VERSION 5.8 ;
BUSBITCHARS "[]" ;
DIVIDERCHAR "/" ;
UNITS
    DATABASE MICRONS 1000 ;
END UNITS

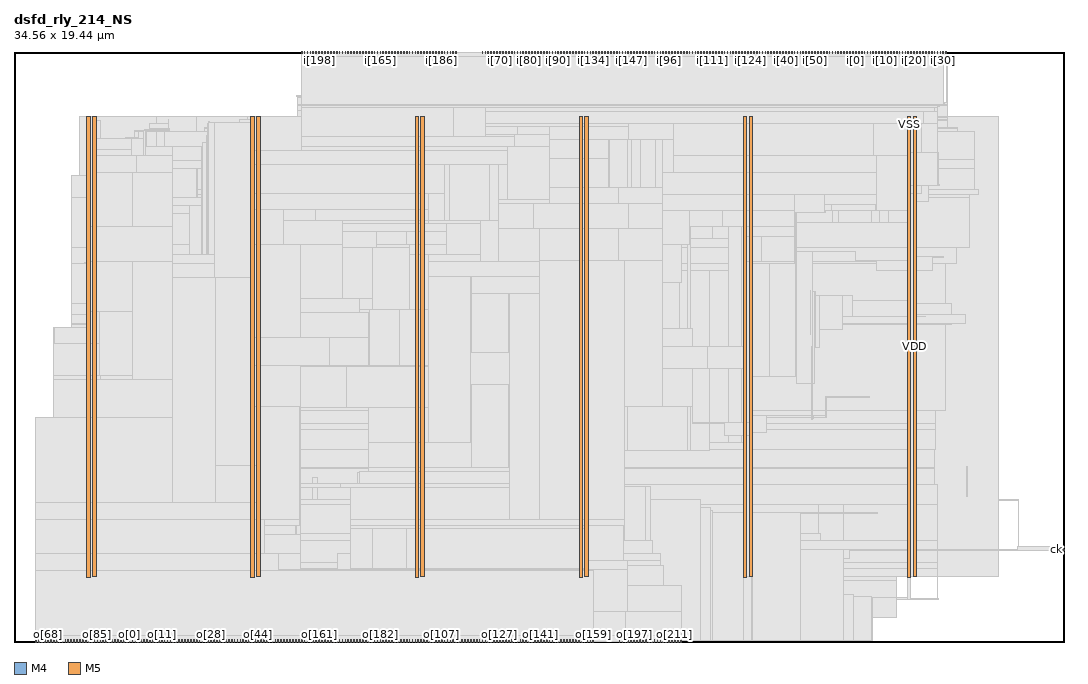
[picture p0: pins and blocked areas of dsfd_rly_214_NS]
MACRO dsfd_rly_214_NS
  FOREIGN dsfd_rly_214_NS 0 0 ;
  CLASS BLOCK ;
  SIZE 34.56 BY 19.44 ;
  PIN ck
    DIRECTION INPUT ;
    USE SIGNAL ;
    PORT
      LAYER M4 ;
        RECT  34.476 3.024 34.56 3.048 ;
    END
  END ck
  PIN i[0]
    DIRECTION INPUT ;
    USE SIGNAL ;
    PORT
      LAYER M5 ;
        RECT  27.696 19.356 27.72 19.44 ;
    END
  END i[0]
  PIN i[100]
    DIRECTION INPUT ;
    USE SIGNAL ;
    PORT
      LAYER M5 ;
        RECT  21.936 19.356 21.96 19.44 ;
    END
  END i[100]
  PIN i[101]
    DIRECTION INPUT ;
    USE SIGNAL ;
    PORT
      LAYER M5 ;
        RECT  22.032 19.356 22.056 19.44 ;
    END
  END i[101]
  PIN i[102]
    DIRECTION INPUT ;
    USE SIGNAL ;
    PORT
      LAYER M5 ;
        RECT  22.128 19.356 22.152 19.44 ;
    END
  END i[102]
  PIN i[103]
    DIRECTION INPUT ;
    USE SIGNAL ;
    PORT
      LAYER M5 ;
        RECT  22.224 19.356 22.248 19.44 ;
    END
  END i[103]
  PIN i[104]
    DIRECTION INPUT ;
    USE SIGNAL ;
    PORT
      LAYER M5 ;
        RECT  22.32 19.356 22.344 19.44 ;
    END
  END i[104]
  PIN i[105]
    DIRECTION INPUT ;
    USE SIGNAL ;
    PORT
      LAYER M5 ;
        RECT  22.416 19.356 22.44 19.44 ;
    END
  END i[105]
  PIN i[106]
    DIRECTION INPUT ;
    USE SIGNAL ;
    PORT
      LAYER M5 ;
        RECT  22.512 19.356 22.536 19.44 ;
    END
  END i[106]
  PIN i[107]
    DIRECTION INPUT ;
    USE SIGNAL ;
    PORT
      LAYER M5 ;
        RECT  22.608 19.356 22.632 19.44 ;
    END
  END i[107]
  PIN i[108]
    DIRECTION INPUT ;
    USE SIGNAL ;
    PORT
      LAYER M5 ;
        RECT  22.704 19.356 22.728 19.44 ;
    END
  END i[108]
  PIN i[109]
    DIRECTION INPUT ;
    USE SIGNAL ;
    PORT
      LAYER M5 ;
        RECT  22.8 19.356 22.824 19.44 ;
    END
  END i[109]
  PIN i[10]
    DIRECTION INPUT ;
    USE SIGNAL ;
    PORT
      LAYER M5 ;
        RECT  28.656 19.356 28.68 19.44 ;
    END
  END i[10]
  PIN i[110]
    DIRECTION INPUT ;
    USE SIGNAL ;
    PORT
      LAYER M5 ;
        RECT  22.896 19.356 22.92 19.44 ;
    END
  END i[110]
  PIN i[111]
    DIRECTION INPUT ;
    USE SIGNAL ;
    PORT
      LAYER M5 ;
        RECT  22.992 19.356 23.016 19.44 ;
    END
  END i[111]
  PIN i[112]
    DIRECTION INPUT ;
    USE SIGNAL ;
    PORT
      LAYER M5 ;
        RECT  23.088 19.356 23.112 19.44 ;
    END
  END i[112]
  PIN i[113]
    DIRECTION INPUT ;
    USE SIGNAL ;
    PORT
      LAYER M5 ;
        RECT  23.184 19.356 23.208 19.44 ;
    END
  END i[113]
  PIN i[114]
    DIRECTION INPUT ;
    USE SIGNAL ;
    PORT
      LAYER M5 ;
        RECT  23.28 19.356 23.304 19.44 ;
    END
  END i[114]
  PIN i[115]
    DIRECTION INPUT ;
    USE SIGNAL ;
    PORT
      LAYER M5 ;
        RECT  23.376 19.356 23.4 19.44 ;
    END
  END i[115]
  PIN i[116]
    DIRECTION INPUT ;
    USE SIGNAL ;
    PORT
      LAYER M5 ;
        RECT  23.472 19.356 23.496 19.44 ;
    END
  END i[116]
  PIN i[117]
    DIRECTION INPUT ;
    USE SIGNAL ;
    PORT
      LAYER M5 ;
        RECT  23.568 19.356 23.592 19.44 ;
    END
  END i[117]
  PIN i[118]
    DIRECTION INPUT ;
    USE SIGNAL ;
    PORT
      LAYER M5 ;
        RECT  23.664 19.356 23.688 19.44 ;
    END
  END i[118]
  PIN i[119]
    DIRECTION INPUT ;
    USE SIGNAL ;
    PORT
      LAYER M5 ;
        RECT  23.76 19.356 23.784 19.44 ;
    END
  END i[119]
  PIN i[11]
    DIRECTION INPUT ;
    USE SIGNAL ;
    PORT
      LAYER M5 ;
        RECT  28.752 19.356 28.776 19.44 ;
    END
  END i[11]
  PIN i[120]
    DIRECTION INPUT ;
    USE SIGNAL ;
    PORT
      LAYER M5 ;
        RECT  23.856 19.356 23.88 19.44 ;
    END
  END i[120]
  PIN i[121]
    DIRECTION INPUT ;
    USE SIGNAL ;
    PORT
      LAYER M5 ;
        RECT  23.952 19.356 23.976 19.44 ;
    END
  END i[121]
  PIN i[122]
    DIRECTION INPUT ;
    USE SIGNAL ;
    PORT
      LAYER M5 ;
        RECT  24.048 19.356 24.072 19.44 ;
    END
  END i[122]
  PIN i[123]
    DIRECTION INPUT ;
    USE SIGNAL ;
    PORT
      LAYER M5 ;
        RECT  24.144 19.356 24.168 19.44 ;
    END
  END i[123]
  PIN i[124]
    DIRECTION INPUT ;
    USE SIGNAL ;
    PORT
      LAYER M5 ;
        RECT  24.24 19.356 24.264 19.44 ;
    END
  END i[124]
  PIN i[125]
    DIRECTION INPUT ;
    USE SIGNAL ;
    PORT
      LAYER M5 ;
        RECT  24.336 19.356 24.36 19.44 ;
    END
  END i[125]
  PIN i[126]
    DIRECTION INPUT ;
    USE SIGNAL ;
    PORT
      LAYER M5 ;
        RECT  24.432 19.356 24.456 19.44 ;
    END
  END i[126]
  PIN i[127]
    DIRECTION INPUT ;
    USE SIGNAL ;
    PORT
      LAYER M5 ;
        RECT  24.528 19.356 24.552 19.44 ;
    END
  END i[127]
  PIN i[128]
    DIRECTION INPUT ;
    USE SIGNAL ;
    PORT
      LAYER M5 ;
        RECT  18.48 19.356 18.504 19.44 ;
    END
  END i[128]
  PIN i[129]
    DIRECTION INPUT ;
    USE SIGNAL ;
    PORT
      LAYER M5 ;
        RECT  18.576 19.356 18.6 19.44 ;
    END
  END i[129]
  PIN i[12]
    DIRECTION INPUT ;
    USE SIGNAL ;
    PORT
      LAYER M5 ;
        RECT  28.848 19.356 28.872 19.44 ;
    END
  END i[12]
  PIN i[130]
    DIRECTION INPUT ;
    USE SIGNAL ;
    PORT
      LAYER M5 ;
        RECT  18.672 19.356 18.696 19.44 ;
    END
  END i[130]
  PIN i[131]
    DIRECTION INPUT ;
    USE SIGNAL ;
    PORT
      LAYER M5 ;
        RECT  18.768 19.356 18.792 19.44 ;
    END
  END i[131]
  PIN i[132]
    DIRECTION INPUT ;
    USE SIGNAL ;
    PORT
      LAYER M5 ;
        RECT  18.864 19.356 18.888 19.44 ;
    END
  END i[132]
  PIN i[133]
    DIRECTION INPUT ;
    USE SIGNAL ;
    PORT
      LAYER M5 ;
        RECT  18.96 19.356 18.984 19.44 ;
    END
  END i[133]
  PIN i[134]
    DIRECTION INPUT ;
    USE SIGNAL ;
    PORT
      LAYER M5 ;
        RECT  19.056 19.356 19.08 19.44 ;
    END
  END i[134]
  PIN i[135]
    DIRECTION INPUT ;
    USE SIGNAL ;
    PORT
      LAYER M5 ;
        RECT  19.152 19.356 19.176 19.44 ;
    END
  END i[135]
  PIN i[136]
    DIRECTION INPUT ;
    USE SIGNAL ;
    PORT
      LAYER M5 ;
        RECT  19.248 19.356 19.272 19.44 ;
    END
  END i[136]
  PIN i[137]
    DIRECTION INPUT ;
    USE SIGNAL ;
    PORT
      LAYER M5 ;
        RECT  19.344 19.356 19.368 19.44 ;
    END
  END i[137]
  PIN i[138]
    DIRECTION INPUT ;
    USE SIGNAL ;
    PORT
      LAYER M5 ;
        RECT  19.44 19.356 19.464 19.44 ;
    END
  END i[138]
  PIN i[139]
    DIRECTION INPUT ;
    USE SIGNAL ;
    PORT
      LAYER M5 ;
        RECT  19.536 19.356 19.56 19.44 ;
    END
  END i[139]
  PIN i[13]
    DIRECTION INPUT ;
    USE SIGNAL ;
    PORT
      LAYER M5 ;
        RECT  28.944 19.356 28.968 19.44 ;
    END
  END i[13]
  PIN i[140]
    DIRECTION INPUT ;
    USE SIGNAL ;
    PORT
      LAYER M5 ;
        RECT  19.632 19.356 19.656 19.44 ;
    END
  END i[140]
  PIN i[141]
    DIRECTION INPUT ;
    USE SIGNAL ;
    PORT
      LAYER M5 ;
        RECT  19.728 19.356 19.752 19.44 ;
    END
  END i[141]
  PIN i[142]
    DIRECTION INPUT ;
    USE SIGNAL ;
    PORT
      LAYER M5 ;
        RECT  19.824 19.356 19.848 19.44 ;
    END
  END i[142]
  PIN i[143]
    DIRECTION INPUT ;
    USE SIGNAL ;
    PORT
      LAYER M5 ;
        RECT  19.92 19.356 19.944 19.44 ;
    END
  END i[143]
  PIN i[144]
    DIRECTION INPUT ;
    USE SIGNAL ;
    PORT
      LAYER M5 ;
        RECT  20.016 19.356 20.04 19.44 ;
    END
  END i[144]
  PIN i[145]
    DIRECTION INPUT ;
    USE SIGNAL ;
    PORT
      LAYER M5 ;
        RECT  20.112 19.356 20.136 19.44 ;
    END
  END i[145]
  PIN i[146]
    DIRECTION INPUT ;
    USE SIGNAL ;
    PORT
      LAYER M5 ;
        RECT  20.208 19.356 20.232 19.44 ;
    END
  END i[146]
  PIN i[147]
    DIRECTION INPUT ;
    USE SIGNAL ;
    PORT
      LAYER M5 ;
        RECT  20.304 19.356 20.328 19.44 ;
    END
  END i[147]
  PIN i[148]
    DIRECTION INPUT ;
    USE SIGNAL ;
    PORT
      LAYER M5 ;
        RECT  20.4 19.356 20.424 19.44 ;
    END
  END i[148]
  PIN i[149]
    DIRECTION INPUT ;
    USE SIGNAL ;
    PORT
      LAYER M5 ;
        RECT  20.496 19.356 20.52 19.44 ;
    END
  END i[149]
  PIN i[14]
    DIRECTION INPUT ;
    USE SIGNAL ;
    PORT
      LAYER M5 ;
        RECT  29.04 19.356 29.064 19.44 ;
    END
  END i[14]
  PIN i[150]
    DIRECTION INPUT ;
    USE SIGNAL ;
    PORT
      LAYER M5 ;
        RECT  20.592 19.356 20.616 19.44 ;
    END
  END i[150]
  PIN i[151]
    DIRECTION INPUT ;
    USE SIGNAL ;
    PORT
      LAYER M5 ;
        RECT  20.688 19.356 20.712 19.44 ;
    END
  END i[151]
  PIN i[152]
    DIRECTION INPUT ;
    USE SIGNAL ;
    PORT
      LAYER M5 ;
        RECT  20.784 19.356 20.808 19.44 ;
    END
  END i[152]
  PIN i[153]
    DIRECTION INPUT ;
    USE SIGNAL ;
    PORT
      LAYER M5 ;
        RECT  20.88 19.356 20.904 19.44 ;
    END
  END i[153]
  PIN i[154]
    DIRECTION INPUT ;
    USE SIGNAL ;
    PORT
      LAYER M5 ;
        RECT  20.976 19.356 21 19.44 ;
    END
  END i[154]
  PIN i[155]
    DIRECTION INPUT ;
    USE SIGNAL ;
    PORT
      LAYER M5 ;
        RECT  21.072 19.356 21.096 19.44 ;
    END
  END i[155]
  PIN i[156]
    DIRECTION INPUT ;
    USE SIGNAL ;
    PORT
      LAYER M5 ;
        RECT  21.168 19.356 21.192 19.44 ;
    END
  END i[156]
  PIN i[157]
    DIRECTION INPUT ;
    USE SIGNAL ;
    PORT
      LAYER M5 ;
        RECT  21.264 19.356 21.288 19.44 ;
    END
  END i[157]
  PIN i[158]
    DIRECTION INPUT ;
    USE SIGNAL ;
    PORT
      LAYER M5 ;
        RECT  21.36 19.356 21.384 19.44 ;
    END
  END i[158]
  PIN i[159]
    DIRECTION INPUT ;
    USE SIGNAL ;
    PORT
      LAYER M5 ;
        RECT  21.456 19.356 21.48 19.44 ;
    END
  END i[159]
  PIN i[15]
    DIRECTION INPUT ;
    USE SIGNAL ;
    PORT
      LAYER M5 ;
        RECT  29.136 19.356 29.16 19.44 ;
    END
  END i[15]
  PIN i[160]
    DIRECTION INPUT ;
    USE SIGNAL ;
    PORT
      LAYER M5 ;
        RECT  11.568 19.356 11.592 19.44 ;
    END
  END i[160]
  PIN i[161]
    DIRECTION INPUT ;
    USE SIGNAL ;
    PORT
      LAYER M5 ;
        RECT  11.664 19.356 11.688 19.44 ;
    END
  END i[161]
  PIN i[162]
    DIRECTION INPUT ;
    USE SIGNAL ;
    PORT
      LAYER M5 ;
        RECT  11.76 19.356 11.784 19.44 ;
    END
  END i[162]
  PIN i[163]
    DIRECTION INPUT ;
    USE SIGNAL ;
    PORT
      LAYER M5 ;
        RECT  11.856 19.356 11.88 19.44 ;
    END
  END i[163]
  PIN i[164]
    DIRECTION INPUT ;
    USE SIGNAL ;
    PORT
      LAYER M5 ;
        RECT  11.952 19.356 11.976 19.44 ;
    END
  END i[164]
  PIN i[165]
    DIRECTION INPUT ;
    USE SIGNAL ;
    PORT
      LAYER M5 ;
        RECT  12.048 19.356 12.072 19.44 ;
    END
  END i[165]
  PIN i[166]
    DIRECTION INPUT ;
    USE SIGNAL ;
    PORT
      LAYER M5 ;
        RECT  12.144 19.356 12.168 19.44 ;
    END
  END i[166]
  PIN i[167]
    DIRECTION INPUT ;
    USE SIGNAL ;
    PORT
      LAYER M5 ;
        RECT  12.24 19.356 12.264 19.44 ;
    END
  END i[167]
  PIN i[168]
    DIRECTION INPUT ;
    USE SIGNAL ;
    PORT
      LAYER M5 ;
        RECT  12.336 19.356 12.36 19.44 ;
    END
  END i[168]
  PIN i[169]
    DIRECTION INPUT ;
    USE SIGNAL ;
    PORT
      LAYER M5 ;
        RECT  12.432 19.356 12.456 19.44 ;
    END
  END i[169]
  PIN i[16]
    DIRECTION INPUT ;
    USE SIGNAL ;
    PORT
      LAYER M5 ;
        RECT  29.232 19.356 29.256 19.44 ;
    END
  END i[16]
  PIN i[170]
    DIRECTION INPUT ;
    USE SIGNAL ;
    PORT
      LAYER M5 ;
        RECT  12.528 19.356 12.552 19.44 ;
    END
  END i[170]
  PIN i[171]
    DIRECTION INPUT ;
    USE SIGNAL ;
    PORT
      LAYER M5 ;
        RECT  12.624 19.356 12.648 19.44 ;
    END
  END i[171]
  PIN i[172]
    DIRECTION INPUT ;
    USE SIGNAL ;
    PORT
      LAYER M5 ;
        RECT  12.72 19.356 12.744 19.44 ;
    END
  END i[172]
  PIN i[173]
    DIRECTION INPUT ;
    USE SIGNAL ;
    PORT
      LAYER M5 ;
        RECT  12.816 19.356 12.84 19.44 ;
    END
  END i[173]
  PIN i[174]
    DIRECTION INPUT ;
    USE SIGNAL ;
    PORT
      LAYER M5 ;
        RECT  12.912 19.356 12.936 19.44 ;
    END
  END i[174]
  PIN i[175]
    DIRECTION INPUT ;
    USE SIGNAL ;
    PORT
      LAYER M5 ;
        RECT  13.008 19.356 13.032 19.44 ;
    END
  END i[175]
  PIN i[176]
    DIRECTION INPUT ;
    USE SIGNAL ;
    PORT
      LAYER M5 ;
        RECT  13.104 19.356 13.128 19.44 ;
    END
  END i[176]
  PIN i[177]
    DIRECTION INPUT ;
    USE SIGNAL ;
    PORT
      LAYER M5 ;
        RECT  13.2 19.356 13.224 19.44 ;
    END
  END i[177]
  PIN i[178]
    DIRECTION INPUT ;
    USE SIGNAL ;
    PORT
      LAYER M5 ;
        RECT  13.296 19.356 13.32 19.44 ;
    END
  END i[178]
  PIN i[179]
    DIRECTION INPUT ;
    USE SIGNAL ;
    PORT
      LAYER M5 ;
        RECT  13.392 19.356 13.416 19.44 ;
    END
  END i[179]
  PIN i[17]
    DIRECTION INPUT ;
    USE SIGNAL ;
    PORT
      LAYER M5 ;
        RECT  29.328 19.356 29.352 19.44 ;
    END
  END i[17]
  PIN i[180]
    DIRECTION INPUT ;
    USE SIGNAL ;
    PORT
      LAYER M5 ;
        RECT  13.488 19.356 13.512 19.44 ;
    END
  END i[180]
  PIN i[181]
    DIRECTION INPUT ;
    USE SIGNAL ;
    PORT
      LAYER M5 ;
        RECT  13.584 19.356 13.608 19.44 ;
    END
  END i[181]
  PIN i[182]
    DIRECTION INPUT ;
    USE SIGNAL ;
    PORT
      LAYER M5 ;
        RECT  13.68 19.356 13.704 19.44 ;
    END
  END i[182]
  PIN i[183]
    DIRECTION INPUT ;
    USE SIGNAL ;
    PORT
      LAYER M5 ;
        RECT  13.776 19.356 13.8 19.44 ;
    END
  END i[183]
  PIN i[184]
    DIRECTION INPUT ;
    USE SIGNAL ;
    PORT
      LAYER M5 ;
        RECT  13.872 19.356 13.896 19.44 ;
    END
  END i[184]
  PIN i[185]
    DIRECTION INPUT ;
    USE SIGNAL ;
    PORT
      LAYER M5 ;
        RECT  13.968 19.356 13.992 19.44 ;
    END
  END i[185]
  PIN i[186]
    DIRECTION INPUT ;
    USE SIGNAL ;
    PORT
      LAYER M5 ;
        RECT  14.064 19.356 14.088 19.44 ;
    END
  END i[186]
  PIN i[187]
    DIRECTION INPUT ;
    USE SIGNAL ;
    PORT
      LAYER M5 ;
        RECT  14.16 19.356 14.184 19.44 ;
    END
  END i[187]
  PIN i[188]
    DIRECTION INPUT ;
    USE SIGNAL ;
    PORT
      LAYER M5 ;
        RECT  14.256 19.356 14.28 19.44 ;
    END
  END i[188]
  PIN i[189]
    DIRECTION INPUT ;
    USE SIGNAL ;
    PORT
      LAYER M5 ;
        RECT  14.352 19.356 14.376 19.44 ;
    END
  END i[189]
  PIN i[18]
    DIRECTION INPUT ;
    USE SIGNAL ;
    PORT
      LAYER M5 ;
        RECT  29.424 19.356 29.448 19.44 ;
    END
  END i[18]
  PIN i[190]
    DIRECTION INPUT ;
    USE SIGNAL ;
    PORT
      LAYER M5 ;
        RECT  14.448 19.356 14.472 19.44 ;
    END
  END i[190]
  PIN i[191]
    DIRECTION INPUT ;
    USE SIGNAL ;
    PORT
      LAYER M5 ;
        RECT  14.544 19.356 14.568 19.44 ;
    END
  END i[191]
  PIN i[192]
    DIRECTION INPUT ;
    USE SIGNAL ;
    PORT
      LAYER M5 ;
        RECT  9.456 19.356 9.48 19.44 ;
    END
  END i[192]
  PIN i[193]
    DIRECTION INPUT ;
    USE SIGNAL ;
    PORT
      LAYER M5 ;
        RECT  9.552 19.356 9.576 19.44 ;
    END
  END i[193]
  PIN i[194]
    DIRECTION INPUT ;
    USE SIGNAL ;
    PORT
      LAYER M5 ;
        RECT  9.648 19.356 9.672 19.44 ;
    END
  END i[194]
  PIN i[195]
    DIRECTION INPUT ;
    USE SIGNAL ;
    PORT
      LAYER M5 ;
        RECT  9.744 19.356 9.768 19.44 ;
    END
  END i[195]
  PIN i[196]
    DIRECTION INPUT ;
    USE SIGNAL ;
    PORT
      LAYER M5 ;
        RECT  9.84 19.356 9.864 19.44 ;
    END
  END i[196]
  PIN i[197]
    DIRECTION INPUT ;
    USE SIGNAL ;
    PORT
      LAYER M5 ;
        RECT  9.936 19.356 9.96 19.44 ;
    END
  END i[197]
  PIN i[198]
    DIRECTION INPUT ;
    USE SIGNAL ;
    PORT
      LAYER M5 ;
        RECT  10.032 19.356 10.056 19.44 ;
    END
  END i[198]
  PIN i[199]
    DIRECTION INPUT ;
    USE SIGNAL ;
    PORT
      LAYER M5 ;
        RECT  10.128 19.356 10.152 19.44 ;
    END
  END i[199]
  PIN i[19]
    DIRECTION INPUT ;
    USE SIGNAL ;
    PORT
      LAYER M5 ;
        RECT  29.52 19.356 29.544 19.44 ;
    END
  END i[19]
  PIN i[1]
    DIRECTION INPUT ;
    USE SIGNAL ;
    PORT
      LAYER M5 ;
        RECT  27.792 19.356 27.816 19.44 ;
    END
  END i[1]
  PIN i[200]
    DIRECTION INPUT ;
    USE SIGNAL ;
    PORT
      LAYER M5 ;
        RECT  10.224 19.356 10.248 19.44 ;
    END
  END i[200]
  PIN i[201]
    DIRECTION INPUT ;
    USE SIGNAL ;
    PORT
      LAYER M5 ;
        RECT  10.32 19.356 10.344 19.44 ;
    END
  END i[201]
  PIN i[202]
    DIRECTION INPUT ;
    USE SIGNAL ;
    PORT
      LAYER M5 ;
        RECT  10.416 19.356 10.44 19.44 ;
    END
  END i[202]
  PIN i[203]
    DIRECTION INPUT ;
    USE SIGNAL ;
    PORT
      LAYER M5 ;
        RECT  10.512 19.356 10.536 19.44 ;
    END
  END i[203]
  PIN i[204]
    DIRECTION INPUT ;
    USE SIGNAL ;
    PORT
      LAYER M5 ;
        RECT  10.608 19.356 10.632 19.44 ;
    END
  END i[204]
  PIN i[205]
    DIRECTION INPUT ;
    USE SIGNAL ;
    PORT
      LAYER M5 ;
        RECT  10.704 19.356 10.728 19.44 ;
    END
  END i[205]
  PIN i[206]
    DIRECTION INPUT ;
    USE SIGNAL ;
    PORT
      LAYER M5 ;
        RECT  10.8 19.356 10.824 19.44 ;
    END
  END i[206]
  PIN i[207]
    DIRECTION INPUT ;
    USE SIGNAL ;
    PORT
      LAYER M5 ;
        RECT  10.896 19.356 10.92 19.44 ;
    END
  END i[207]
  PIN i[208]
    DIRECTION INPUT ;
    USE SIGNAL ;
    PORT
      LAYER M5 ;
        RECT  10.992 19.356 11.016 19.44 ;
    END
  END i[208]
  PIN i[209]
    DIRECTION INPUT ;
    USE SIGNAL ;
    PORT
      LAYER M5 ;
        RECT  11.088 19.356 11.112 19.44 ;
    END
  END i[209]
  PIN i[20]
    DIRECTION INPUT ;
    USE SIGNAL ;
    PORT
      LAYER M5 ;
        RECT  29.616 19.356 29.64 19.44 ;
    END
  END i[20]
  PIN i[210]
    DIRECTION INPUT ;
    USE SIGNAL ;
    PORT
      LAYER M5 ;
        RECT  11.184 19.356 11.208 19.44 ;
    END
  END i[210]
  PIN i[211]
    DIRECTION INPUT ;
    USE SIGNAL ;
    PORT
      LAYER M5 ;
        RECT  11.28 19.356 11.304 19.44 ;
    END
  END i[211]
  PIN i[212]
    DIRECTION INPUT ;
    USE SIGNAL ;
    PORT
      LAYER M5 ;
        RECT  11.376 19.356 11.4 19.44 ;
    END
  END i[212]
  PIN i[213]
    DIRECTION INPUT ;
    USE SIGNAL ;
    PORT
      LAYER M5 ;
        RECT  11.472 19.356 11.496 19.44 ;
    END
  END i[213]
  PIN i[21]
    DIRECTION INPUT ;
    USE SIGNAL ;
    PORT
      LAYER M5 ;
        RECT  29.712 19.356 29.736 19.44 ;
    END
  END i[21]
  PIN i[22]
    DIRECTION INPUT ;
    USE SIGNAL ;
    PORT
      LAYER M5 ;
        RECT  29.808 19.356 29.832 19.44 ;
    END
  END i[22]
  PIN i[23]
    DIRECTION INPUT ;
    USE SIGNAL ;
    PORT
      LAYER M5 ;
        RECT  29.904 19.356 29.928 19.44 ;
    END
  END i[23]
  PIN i[24]
    DIRECTION INPUT ;
    USE SIGNAL ;
    PORT
      LAYER M5 ;
        RECT  30 19.356 30.024 19.44 ;
    END
  END i[24]
  PIN i[25]
    DIRECTION INPUT ;
    USE SIGNAL ;
    PORT
      LAYER M5 ;
        RECT  30.096 19.356 30.12 19.44 ;
    END
  END i[25]
  PIN i[26]
    DIRECTION INPUT ;
    USE SIGNAL ;
    PORT
      LAYER M5 ;
        RECT  30.192 19.356 30.216 19.44 ;
    END
  END i[26]
  PIN i[27]
    DIRECTION INPUT ;
    USE SIGNAL ;
    PORT
      LAYER M5 ;
        RECT  30.288 19.356 30.312 19.44 ;
    END
  END i[27]
  PIN i[28]
    DIRECTION INPUT ;
    USE SIGNAL ;
    PORT
      LAYER M5 ;
        RECT  30.384 19.356 30.408 19.44 ;
    END
  END i[28]
  PIN i[29]
    DIRECTION INPUT ;
    USE SIGNAL ;
    PORT
      LAYER M5 ;
        RECT  30.48 19.356 30.504 19.44 ;
    END
  END i[29]
  PIN i[2]
    DIRECTION INPUT ;
    USE SIGNAL ;
    PORT
      LAYER M5 ;
        RECT  27.888 19.356 27.912 19.44 ;
    END
  END i[2]
  PIN i[30]
    DIRECTION INPUT ;
    USE SIGNAL ;
    PORT
      LAYER M5 ;
        RECT  30.576 19.356 30.6 19.44 ;
    END
  END i[30]
  PIN i[31]
    DIRECTION INPUT ;
    USE SIGNAL ;
    PORT
      LAYER M5 ;
        RECT  30.672 19.356 30.696 19.44 ;
    END
  END i[31]
  PIN i[32]
    DIRECTION INPUT ;
    USE SIGNAL ;
    PORT
      LAYER M5 ;
        RECT  24.624 19.356 24.648 19.44 ;
    END
  END i[32]
  PIN i[33]
    DIRECTION INPUT ;
    USE SIGNAL ;
    PORT
      LAYER M5 ;
        RECT  24.72 19.356 24.744 19.44 ;
    END
  END i[33]
  PIN i[34]
    DIRECTION INPUT ;
    USE SIGNAL ;
    PORT
      LAYER M5 ;
        RECT  24.816 19.356 24.84 19.44 ;
    END
  END i[34]
  PIN i[35]
    DIRECTION INPUT ;
    USE SIGNAL ;
    PORT
      LAYER M5 ;
        RECT  24.912 19.356 24.936 19.44 ;
    END
  END i[35]
  PIN i[36]
    DIRECTION INPUT ;
    USE SIGNAL ;
    PORT
      LAYER M5 ;
        RECT  25.008 19.356 25.032 19.44 ;
    END
  END i[36]
  PIN i[37]
    DIRECTION INPUT ;
    USE SIGNAL ;
    PORT
      LAYER M5 ;
        RECT  25.104 19.356 25.128 19.44 ;
    END
  END i[37]
  PIN i[38]
    DIRECTION INPUT ;
    USE SIGNAL ;
    PORT
      LAYER M5 ;
        RECT  25.2 19.356 25.224 19.44 ;
    END
  END i[38]
  PIN i[39]
    DIRECTION INPUT ;
    USE SIGNAL ;
    PORT
      LAYER M5 ;
        RECT  25.296 19.356 25.32 19.44 ;
    END
  END i[39]
  PIN i[3]
    DIRECTION INPUT ;
    USE SIGNAL ;
    PORT
      LAYER M5 ;
        RECT  27.984 19.356 28.008 19.44 ;
    END
  END i[3]
  PIN i[40]
    DIRECTION INPUT ;
    USE SIGNAL ;
    PORT
      LAYER M5 ;
        RECT  25.392 19.356 25.416 19.44 ;
    END
  END i[40]
  PIN i[41]
    DIRECTION INPUT ;
    USE SIGNAL ;
    PORT
      LAYER M5 ;
        RECT  25.488 19.356 25.512 19.44 ;
    END
  END i[41]
  PIN i[42]
    DIRECTION INPUT ;
    USE SIGNAL ;
    PORT
      LAYER M5 ;
        RECT  25.584 19.356 25.608 19.44 ;
    END
  END i[42]
  PIN i[43]
    DIRECTION INPUT ;
    USE SIGNAL ;
    PORT
      LAYER M5 ;
        RECT  25.68 19.356 25.704 19.44 ;
    END
  END i[43]
  PIN i[44]
    DIRECTION INPUT ;
    USE SIGNAL ;
    PORT
      LAYER M5 ;
        RECT  25.776 19.356 25.8 19.44 ;
    END
  END i[44]
  PIN i[45]
    DIRECTION INPUT ;
    USE SIGNAL ;
    PORT
      LAYER M5 ;
        RECT  25.872 19.356 25.896 19.44 ;
    END
  END i[45]
  PIN i[46]
    DIRECTION INPUT ;
    USE SIGNAL ;
    PORT
      LAYER M5 ;
        RECT  25.968 19.356 25.992 19.44 ;
    END
  END i[46]
  PIN i[47]
    DIRECTION INPUT ;
    USE SIGNAL ;
    PORT
      LAYER M5 ;
        RECT  26.064 19.356 26.088 19.44 ;
    END
  END i[47]
  PIN i[48]
    DIRECTION INPUT ;
    USE SIGNAL ;
    PORT
      LAYER M5 ;
        RECT  26.16 19.356 26.184 19.44 ;
    END
  END i[48]
  PIN i[49]
    DIRECTION INPUT ;
    USE SIGNAL ;
    PORT
      LAYER M5 ;
        RECT  26.256 19.356 26.28 19.44 ;
    END
  END i[49]
  PIN i[4]
    DIRECTION INPUT ;
    USE SIGNAL ;
    PORT
      LAYER M5 ;
        RECT  28.08 19.356 28.104 19.44 ;
    END
  END i[4]
  PIN i[50]
    DIRECTION INPUT ;
    USE SIGNAL ;
    PORT
      LAYER M5 ;
        RECT  26.352 19.356 26.376 19.44 ;
    END
  END i[50]
  PIN i[51]
    DIRECTION INPUT ;
    USE SIGNAL ;
    PORT
      LAYER M5 ;
        RECT  26.448 19.356 26.472 19.44 ;
    END
  END i[51]
  PIN i[52]
    DIRECTION INPUT ;
    USE SIGNAL ;
    PORT
      LAYER M5 ;
        RECT  26.544 19.356 26.568 19.44 ;
    END
  END i[52]
  PIN i[53]
    DIRECTION INPUT ;
    USE SIGNAL ;
    PORT
      LAYER M5 ;
        RECT  26.64 19.356 26.664 19.44 ;
    END
  END i[53]
  PIN i[54]
    DIRECTION INPUT ;
    USE SIGNAL ;
    PORT
      LAYER M5 ;
        RECT  26.736 19.356 26.76 19.44 ;
    END
  END i[54]
  PIN i[55]
    DIRECTION INPUT ;
    USE SIGNAL ;
    PORT
      LAYER M5 ;
        RECT  26.832 19.356 26.856 19.44 ;
    END
  END i[55]
  PIN i[56]
    DIRECTION INPUT ;
    USE SIGNAL ;
    PORT
      LAYER M5 ;
        RECT  26.928 19.356 26.952 19.44 ;
    END
  END i[56]
  PIN i[57]
    DIRECTION INPUT ;
    USE SIGNAL ;
    PORT
      LAYER M5 ;
        RECT  27.024 19.356 27.048 19.44 ;
    END
  END i[57]
  PIN i[58]
    DIRECTION INPUT ;
    USE SIGNAL ;
    PORT
      LAYER M5 ;
        RECT  27.12 19.356 27.144 19.44 ;
    END
  END i[58]
  PIN i[59]
    DIRECTION INPUT ;
    USE SIGNAL ;
    PORT
      LAYER M5 ;
        RECT  27.216 19.356 27.24 19.44 ;
    END
  END i[59]
  PIN i[5]
    DIRECTION INPUT ;
    USE SIGNAL ;
    PORT
      LAYER M5 ;
        RECT  28.176 19.356 28.2 19.44 ;
    END
  END i[5]
  PIN i[60]
    DIRECTION INPUT ;
    USE SIGNAL ;
    PORT
      LAYER M5 ;
        RECT  27.312 19.356 27.336 19.44 ;
    END
  END i[60]
  PIN i[61]
    DIRECTION INPUT ;
    USE SIGNAL ;
    PORT
      LAYER M5 ;
        RECT  27.408 19.356 27.432 19.44 ;
    END
  END i[61]
  PIN i[62]
    DIRECTION INPUT ;
    USE SIGNAL ;
    PORT
      LAYER M5 ;
        RECT  27.504 19.356 27.528 19.44 ;
    END
  END i[62]
  PIN i[63]
    DIRECTION INPUT ;
    USE SIGNAL ;
    PORT
      LAYER M5 ;
        RECT  27.6 19.356 27.624 19.44 ;
    END
  END i[63]
  PIN i[64]
    DIRECTION INPUT ;
    USE SIGNAL ;
    PORT
      LAYER M5 ;
        RECT  15.408 19.356 15.432 19.44 ;
    END
  END i[64]
  PIN i[65]
    DIRECTION INPUT ;
    USE SIGNAL ;
    PORT
      LAYER M5 ;
        RECT  15.504 19.356 15.528 19.44 ;
    END
  END i[65]
  PIN i[66]
    DIRECTION INPUT ;
    USE SIGNAL ;
    PORT
      LAYER M5 ;
        RECT  15.6 19.356 15.624 19.44 ;
    END
  END i[66]
  PIN i[67]
    DIRECTION INPUT ;
    USE SIGNAL ;
    PORT
      LAYER M5 ;
        RECT  15.696 19.356 15.72 19.44 ;
    END
  END i[67]
  PIN i[68]
    DIRECTION INPUT ;
    USE SIGNAL ;
    PORT
      LAYER M5 ;
        RECT  15.792 19.356 15.816 19.44 ;
    END
  END i[68]
  PIN i[69]
    DIRECTION INPUT ;
    USE SIGNAL ;
    PORT
      LAYER M5 ;
        RECT  15.888 19.356 15.912 19.44 ;
    END
  END i[69]
  PIN i[6]
    DIRECTION INPUT ;
    USE SIGNAL ;
    PORT
      LAYER M5 ;
        RECT  28.272 19.356 28.296 19.44 ;
    END
  END i[6]
  PIN i[70]
    DIRECTION INPUT ;
    USE SIGNAL ;
    PORT
      LAYER M5 ;
        RECT  15.984 19.356 16.008 19.44 ;
    END
  END i[70]
  PIN i[71]
    DIRECTION INPUT ;
    USE SIGNAL ;
    PORT
      LAYER M5 ;
        RECT  16.08 19.356 16.104 19.44 ;
    END
  END i[71]
  PIN i[72]
    DIRECTION INPUT ;
    USE SIGNAL ;
    PORT
      LAYER M5 ;
        RECT  16.176 19.356 16.2 19.44 ;
    END
  END i[72]
  PIN i[73]
    DIRECTION INPUT ;
    USE SIGNAL ;
    PORT
      LAYER M5 ;
        RECT  16.272 19.356 16.296 19.44 ;
    END
  END i[73]
  PIN i[74]
    DIRECTION INPUT ;
    USE SIGNAL ;
    PORT
      LAYER M5 ;
        RECT  16.368 19.356 16.392 19.44 ;
    END
  END i[74]
  PIN i[75]
    DIRECTION INPUT ;
    USE SIGNAL ;
    PORT
      LAYER M5 ;
        RECT  16.464 19.356 16.488 19.44 ;
    END
  END i[75]
  PIN i[76]
    DIRECTION INPUT ;
    USE SIGNAL ;
    PORT
      LAYER M5 ;
        RECT  16.56 19.356 16.584 19.44 ;
    END
  END i[76]
  PIN i[77]
    DIRECTION INPUT ;
    USE SIGNAL ;
    PORT
      LAYER M5 ;
        RECT  16.656 19.356 16.68 19.44 ;
    END
  END i[77]
  PIN i[78]
    DIRECTION INPUT ;
    USE SIGNAL ;
    PORT
      LAYER M5 ;
        RECT  16.752 19.356 16.776 19.44 ;
    END
  END i[78]
  PIN i[79]
    DIRECTION INPUT ;
    USE SIGNAL ;
    PORT
      LAYER M5 ;
        RECT  16.848 19.356 16.872 19.44 ;
    END
  END i[79]
  PIN i[7]
    DIRECTION INPUT ;
    USE SIGNAL ;
    PORT
      LAYER M5 ;
        RECT  28.368 19.356 28.392 19.44 ;
    END
  END i[7]
  PIN i[80]
    DIRECTION INPUT ;
    USE SIGNAL ;
    PORT
      LAYER M5 ;
        RECT  16.944 19.356 16.968 19.44 ;
    END
  END i[80]
  PIN i[81]
    DIRECTION INPUT ;
    USE SIGNAL ;
    PORT
      LAYER M5 ;
        RECT  17.04 19.356 17.064 19.44 ;
    END
  END i[81]
  PIN i[82]
    DIRECTION INPUT ;
    USE SIGNAL ;
    PORT
      LAYER M5 ;
        RECT  17.136 19.356 17.16 19.44 ;
    END
  END i[82]
  PIN i[83]
    DIRECTION INPUT ;
    USE SIGNAL ;
    PORT
      LAYER M5 ;
        RECT  17.232 19.356 17.256 19.44 ;
    END
  END i[83]
  PIN i[84]
    DIRECTION INPUT ;
    USE SIGNAL ;
    PORT
      LAYER M5 ;
        RECT  17.328 19.356 17.352 19.44 ;
    END
  END i[84]
  PIN i[85]
    DIRECTION INPUT ;
    USE SIGNAL ;
    PORT
      LAYER M5 ;
        RECT  17.424 19.356 17.448 19.44 ;
    END
  END i[85]
  PIN i[86]
    DIRECTION INPUT ;
    USE SIGNAL ;
    PORT
      LAYER M5 ;
        RECT  17.52 19.356 17.544 19.44 ;
    END
  END i[86]
  PIN i[87]
    DIRECTION INPUT ;
    USE SIGNAL ;
    PORT
      LAYER M5 ;
        RECT  17.616 19.356 17.64 19.44 ;
    END
  END i[87]
  PIN i[88]
    DIRECTION INPUT ;
    USE SIGNAL ;
    PORT
      LAYER M5 ;
        RECT  17.712 19.356 17.736 19.44 ;
    END
  END i[88]
  PIN i[89]
    DIRECTION INPUT ;
    USE SIGNAL ;
    PORT
      LAYER M5 ;
        RECT  17.808 19.356 17.832 19.44 ;
    END
  END i[89]
  PIN i[8]
    DIRECTION INPUT ;
    USE SIGNAL ;
    PORT
      LAYER M5 ;
        RECT  28.464 19.356 28.488 19.44 ;
    END
  END i[8]
  PIN i[90]
    DIRECTION INPUT ;
    USE SIGNAL ;
    PORT
      LAYER M5 ;
        RECT  17.904 19.356 17.928 19.44 ;
    END
  END i[90]
  PIN i[91]
    DIRECTION INPUT ;
    USE SIGNAL ;
    PORT
      LAYER M5 ;
        RECT  18 19.356 18.024 19.44 ;
    END
  END i[91]
  PIN i[92]
    DIRECTION INPUT ;
    USE SIGNAL ;
    PORT
      LAYER M5 ;
        RECT  18.096 19.356 18.12 19.44 ;
    END
  END i[92]
  PIN i[93]
    DIRECTION INPUT ;
    USE SIGNAL ;
    PORT
      LAYER M5 ;
        RECT  18.192 19.356 18.216 19.44 ;
    END
  END i[93]
  PIN i[94]
    DIRECTION INPUT ;
    USE SIGNAL ;
    PORT
      LAYER M5 ;
        RECT  18.288 19.356 18.312 19.44 ;
    END
  END i[94]
  PIN i[95]
    DIRECTION INPUT ;
    USE SIGNAL ;
    PORT
      LAYER M5 ;
        RECT  18.384 19.356 18.408 19.44 ;
    END
  END i[95]
  PIN i[96]
    DIRECTION INPUT ;
    USE SIGNAL ;
    PORT
      LAYER M5 ;
        RECT  21.552 19.356 21.576 19.44 ;
    END
  END i[96]
  PIN i[97]
    DIRECTION INPUT ;
    USE SIGNAL ;
    PORT
      LAYER M5 ;
        RECT  21.648 19.356 21.672 19.44 ;
    END
  END i[97]
  PIN i[98]
    DIRECTION INPUT ;
    USE SIGNAL ;
    PORT
      LAYER M5 ;
        RECT  21.744 19.356 21.768 19.44 ;
    END
  END i[98]
  PIN i[99]
    DIRECTION INPUT ;
    USE SIGNAL ;
    PORT
      LAYER M5 ;
        RECT  21.84 19.356 21.864 19.44 ;
    END
  END i[99]
  PIN i[9]
    DIRECTION INPUT ;
    USE SIGNAL ;
    PORT
      LAYER M5 ;
        RECT  28.56 19.356 28.584 19.44 ;
    END
  END i[9]
  PIN o[0]
    DIRECTION OUTPUT ;
    USE SIGNAL ;
    PORT
      LAYER M5 ;
        RECT  3.792 0 3.816 0.084 ;
    END
  END o[0]
  PIN o[100]
    DIRECTION OUTPUT ;
    USE SIGNAL ;
    PORT
      LAYER M5 ;
        RECT  13.392 0 13.416 0.084 ;
    END
  END o[100]
  PIN o[101]
    DIRECTION OUTPUT ;
    USE SIGNAL ;
    PORT
      LAYER M5 ;
        RECT  13.488 0 13.512 0.084 ;
    END
  END o[101]
  PIN o[102]
    DIRECTION OUTPUT ;
    USE SIGNAL ;
    PORT
      LAYER M5 ;
        RECT  13.584 0 13.608 0.084 ;
    END
  END o[102]
  PIN o[103]
    DIRECTION OUTPUT ;
    USE SIGNAL ;
    PORT
      LAYER M5 ;
        RECT  13.68 0 13.704 0.084 ;
    END
  END o[103]
  PIN o[104]
    DIRECTION OUTPUT ;
    USE SIGNAL ;
    PORT
      LAYER M5 ;
        RECT  13.776 0 13.8 0.084 ;
    END
  END o[104]
  PIN o[105]
    DIRECTION OUTPUT ;
    USE SIGNAL ;
    PORT
      LAYER M5 ;
        RECT  13.872 0 13.896 0.084 ;
    END
  END o[105]
  PIN o[106]
    DIRECTION OUTPUT ;
    USE SIGNAL ;
    PORT
      LAYER M5 ;
        RECT  13.968 0 13.992 0.084 ;
    END
  END o[106]
  PIN o[107]
    DIRECTION OUTPUT ;
    USE SIGNAL ;
    PORT
      LAYER M5 ;
        RECT  14.064 0 14.088 0.084 ;
    END
  END o[107]
  PIN o[108]
    DIRECTION OUTPUT ;
    USE SIGNAL ;
    PORT
      LAYER M5 ;
        RECT  14.16 0 14.184 0.084 ;
    END
  END o[108]
  PIN o[109]
    DIRECTION OUTPUT ;
    USE SIGNAL ;
    PORT
      LAYER M5 ;
        RECT  14.256 0 14.28 0.084 ;
    END
  END o[109]
  PIN o[10]
    DIRECTION OUTPUT ;
    USE SIGNAL ;
    PORT
      LAYER M5 ;
        RECT  4.752 0 4.776 0.084 ;
    END
  END o[10]
  PIN o[110]
    DIRECTION OUTPUT ;
    USE SIGNAL ;
    PORT
      LAYER M5 ;
        RECT  14.352 0 14.376 0.084 ;
    END
  END o[110]
  PIN o[111]
    DIRECTION OUTPUT ;
    USE SIGNAL ;
    PORT
      LAYER M5 ;
        RECT  14.448 0 14.472 0.084 ;
    END
  END o[111]
  PIN o[112]
    DIRECTION OUTPUT ;
    USE SIGNAL ;
    PORT
      LAYER M5 ;
        RECT  14.544 0 14.568 0.084 ;
    END
  END o[112]
  PIN o[113]
    DIRECTION OUTPUT ;
    USE SIGNAL ;
    PORT
      LAYER M5 ;
        RECT  14.64 0 14.664 0.084 ;
    END
  END o[113]
  PIN o[114]
    DIRECTION OUTPUT ;
    USE SIGNAL ;
    PORT
      LAYER M5 ;
        RECT  14.736 0 14.76 0.084 ;
    END
  END o[114]
  PIN o[115]
    DIRECTION OUTPUT ;
    USE SIGNAL ;
    PORT
      LAYER M5 ;
        RECT  14.832 0 14.856 0.084 ;
    END
  END o[115]
  PIN o[116]
    DIRECTION OUTPUT ;
    USE SIGNAL ;
    PORT
      LAYER M5 ;
        RECT  14.928 0 14.952 0.084 ;
    END
  END o[116]
  PIN o[117]
    DIRECTION OUTPUT ;
    USE SIGNAL ;
    PORT
      LAYER M5 ;
        RECT  15.024 0 15.048 0.084 ;
    END
  END o[117]
  PIN o[118]
    DIRECTION OUTPUT ;
    USE SIGNAL ;
    PORT
      LAYER M5 ;
        RECT  15.12 0 15.144 0.084 ;
    END
  END o[118]
  PIN o[119]
    DIRECTION OUTPUT ;
    USE SIGNAL ;
    PORT
      LAYER M5 ;
        RECT  15.216 0 15.24 0.084 ;
    END
  END o[119]
  PIN o[11]
    DIRECTION OUTPUT ;
    USE SIGNAL ;
    PORT
      LAYER M5 ;
        RECT  4.848 0 4.872 0.084 ;
    END
  END o[11]
  PIN o[120]
    DIRECTION OUTPUT ;
    USE SIGNAL ;
    PORT
      LAYER M5 ;
        RECT  15.312 0 15.336 0.084 ;
    END
  END o[120]
  PIN o[121]
    DIRECTION OUTPUT ;
    USE SIGNAL ;
    PORT
      LAYER M5 ;
        RECT  15.408 0 15.432 0.084 ;
    END
  END o[121]
  PIN o[122]
    DIRECTION OUTPUT ;
    USE SIGNAL ;
    PORT
      LAYER M5 ;
        RECT  15.504 0 15.528 0.084 ;
    END
  END o[122]
  PIN o[123]
    DIRECTION OUTPUT ;
    USE SIGNAL ;
    PORT
      LAYER M5 ;
        RECT  15.6 0 15.624 0.084 ;
    END
  END o[123]
  PIN o[124]
    DIRECTION OUTPUT ;
    USE SIGNAL ;
    PORT
      LAYER M5 ;
        RECT  15.696 0 15.72 0.084 ;
    END
  END o[124]
  PIN o[125]
    DIRECTION OUTPUT ;
    USE SIGNAL ;
    PORT
      LAYER M5 ;
        RECT  15.792 0 15.816 0.084 ;
    END
  END o[125]
  PIN o[126]
    DIRECTION OUTPUT ;
    USE SIGNAL ;
    PORT
      LAYER M5 ;
        RECT  15.888 0 15.912 0.084 ;
    END
  END o[126]
  PIN o[127]
    DIRECTION OUTPUT ;
    USE SIGNAL ;
    PORT
      LAYER M5 ;
        RECT  15.984 0 16.008 0.084 ;
    END
  END o[127]
  PIN o[128]
    DIRECTION OUTPUT ;
    USE SIGNAL ;
    PORT
      LAYER M5 ;
        RECT  16.08 0 16.104 0.084 ;
    END
  END o[128]
  PIN o[129]
    DIRECTION OUTPUT ;
    USE SIGNAL ;
    PORT
      LAYER M5 ;
        RECT  16.176 0 16.2 0.084 ;
    END
  END o[129]
  PIN o[12]
    DIRECTION OUTPUT ;
    USE SIGNAL ;
    PORT
      LAYER M5 ;
        RECT  4.944 0 4.968 0.084 ;
    END
  END o[12]
  PIN o[130]
    DIRECTION OUTPUT ;
    USE SIGNAL ;
    PORT
      LAYER M5 ;
        RECT  16.272 0 16.296 0.084 ;
    END
  END o[130]
  PIN o[131]
    DIRECTION OUTPUT ;
    USE SIGNAL ;
    PORT
      LAYER M5 ;
        RECT  16.368 0 16.392 0.084 ;
    END
  END o[131]
  PIN o[132]
    DIRECTION OUTPUT ;
    USE SIGNAL ;
    PORT
      LAYER M5 ;
        RECT  16.464 0 16.488 0.084 ;
    END
  END o[132]
  PIN o[133]
    DIRECTION OUTPUT ;
    USE SIGNAL ;
    PORT
      LAYER M5 ;
        RECT  16.56 0 16.584 0.084 ;
    END
  END o[133]
  PIN o[134]
    DIRECTION OUTPUT ;
    USE SIGNAL ;
    PORT
      LAYER M5 ;
        RECT  16.656 0 16.68 0.084 ;
    END
  END o[134]
  PIN o[135]
    DIRECTION OUTPUT ;
    USE SIGNAL ;
    PORT
      LAYER M5 ;
        RECT  16.752 0 16.776 0.084 ;
    END
  END o[135]
  PIN o[136]
    DIRECTION OUTPUT ;
    USE SIGNAL ;
    PORT
      LAYER M5 ;
        RECT  16.848 0 16.872 0.084 ;
    END
  END o[136]
  PIN o[137]
    DIRECTION OUTPUT ;
    USE SIGNAL ;
    PORT
      LAYER M5 ;
        RECT  16.944 0 16.968 0.084 ;
    END
  END o[137]
  PIN o[138]
    DIRECTION OUTPUT ;
    USE SIGNAL ;
    PORT
      LAYER M5 ;
        RECT  17.04 0 17.064 0.084 ;
    END
  END o[138]
  PIN o[139]
    DIRECTION OUTPUT ;
    USE SIGNAL ;
    PORT
      LAYER M5 ;
        RECT  17.136 0 17.16 0.084 ;
    END
  END o[139]
  PIN o[13]
    DIRECTION OUTPUT ;
    USE SIGNAL ;
    PORT
      LAYER M5 ;
        RECT  5.04 0 5.064 0.084 ;
    END
  END o[13]
  PIN o[140]
    DIRECTION OUTPUT ;
    USE SIGNAL ;
    PORT
      LAYER M5 ;
        RECT  17.232 0 17.256 0.084 ;
    END
  END o[140]
  PIN o[141]
    DIRECTION OUTPUT ;
    USE SIGNAL ;
    PORT
      LAYER M5 ;
        RECT  17.328 0 17.352 0.084 ;
    END
  END o[141]
  PIN o[142]
    DIRECTION OUTPUT ;
    USE SIGNAL ;
    PORT
      LAYER M5 ;
        RECT  17.424 0 17.448 0.084 ;
    END
  END o[142]
  PIN o[143]
    DIRECTION OUTPUT ;
    USE SIGNAL ;
    PORT
      LAYER M5 ;
        RECT  17.52 0 17.544 0.084 ;
    END
  END o[143]
  PIN o[144]
    DIRECTION OUTPUT ;
    USE SIGNAL ;
    PORT
      LAYER M5 ;
        RECT  17.616 0 17.64 0.084 ;
    END
  END o[144]
  PIN o[145]
    DIRECTION OUTPUT ;
    USE SIGNAL ;
    PORT
      LAYER M5 ;
        RECT  17.712 0 17.736 0.084 ;
    END
  END o[145]
  PIN o[146]
    DIRECTION OUTPUT ;
    USE SIGNAL ;
    PORT
      LAYER M5 ;
        RECT  17.808 0 17.832 0.084 ;
    END
  END o[146]
  PIN o[147]
    DIRECTION OUTPUT ;
    USE SIGNAL ;
    PORT
      LAYER M5 ;
        RECT  17.904 0 17.928 0.084 ;
    END
  END o[147]
  PIN o[148]
    DIRECTION OUTPUT ;
    USE SIGNAL ;
    PORT
      LAYER M5 ;
        RECT  18 0 18.024 0.084 ;
    END
  END o[148]
  PIN o[149]
    DIRECTION OUTPUT ;
    USE SIGNAL ;
    PORT
      LAYER M5 ;
        RECT  18.096 0 18.12 0.084 ;
    END
  END o[149]
  PIN o[14]
    DIRECTION OUTPUT ;
    USE SIGNAL ;
    PORT
      LAYER M5 ;
        RECT  5.136 0 5.16 0.084 ;
    END
  END o[14]
  PIN o[150]
    DIRECTION OUTPUT ;
    USE SIGNAL ;
    PORT
      LAYER M5 ;
        RECT  18.192 0 18.216 0.084 ;
    END
  END o[150]
  PIN o[151]
    DIRECTION OUTPUT ;
    USE SIGNAL ;
    PORT
      LAYER M5 ;
        RECT  18.288 0 18.312 0.084 ;
    END
  END o[151]
  PIN o[152]
    DIRECTION OUTPUT ;
    USE SIGNAL ;
    PORT
      LAYER M5 ;
        RECT  18.384 0 18.408 0.084 ;
    END
  END o[152]
  PIN o[153]
    DIRECTION OUTPUT ;
    USE SIGNAL ;
    PORT
      LAYER M5 ;
        RECT  18.48 0 18.504 0.084 ;
    END
  END o[153]
  PIN o[154]
    DIRECTION OUTPUT ;
    USE SIGNAL ;
    PORT
      LAYER M5 ;
        RECT  18.576 0 18.6 0.084 ;
    END
  END o[154]
  PIN o[155]
    DIRECTION OUTPUT ;
    USE SIGNAL ;
    PORT
      LAYER M5 ;
        RECT  18.672 0 18.696 0.084 ;
    END
  END o[155]
  PIN o[156]
    DIRECTION OUTPUT ;
    USE SIGNAL ;
    PORT
      LAYER M5 ;
        RECT  18.768 0 18.792 0.084 ;
    END
  END o[156]
  PIN o[157]
    DIRECTION OUTPUT ;
    USE SIGNAL ;
    PORT
      LAYER M5 ;
        RECT  18.864 0 18.888 0.084 ;
    END
  END o[157]
  PIN o[158]
    DIRECTION OUTPUT ;
    USE SIGNAL ;
    PORT
      LAYER M5 ;
        RECT  18.96 0 18.984 0.084 ;
    END
  END o[158]
  PIN o[159]
    DIRECTION OUTPUT ;
    USE SIGNAL ;
    PORT
      LAYER M5 ;
        RECT  19.056 0 19.08 0.084 ;
    END
  END o[159]
  PIN o[15]
    DIRECTION OUTPUT ;
    USE SIGNAL ;
    PORT
      LAYER M5 ;
        RECT  5.232 0 5.256 0.084 ;
    END
  END o[15]
  PIN o[160]
    DIRECTION OUTPUT ;
    USE SIGNAL ;
    PORT
      LAYER M5 ;
        RECT  9.936 0 9.96 0.084 ;
    END
  END o[160]
  PIN o[161]
    DIRECTION OUTPUT ;
    USE SIGNAL ;
    PORT
      LAYER M5 ;
        RECT  10.032 0 10.056 0.084 ;
    END
  END o[161]
  PIN o[162]
    DIRECTION OUTPUT ;
    USE SIGNAL ;
    PORT
      LAYER M5 ;
        RECT  10.128 0 10.152 0.084 ;
    END
  END o[162]
  PIN o[163]
    DIRECTION OUTPUT ;
    USE SIGNAL ;
    PORT
      LAYER M5 ;
        RECT  10.224 0 10.248 0.084 ;
    END
  END o[163]
  PIN o[164]
    DIRECTION OUTPUT ;
    USE SIGNAL ;
    PORT
      LAYER M5 ;
        RECT  10.32 0 10.344 0.084 ;
    END
  END o[164]
  PIN o[165]
    DIRECTION OUTPUT ;
    USE SIGNAL ;
    PORT
      LAYER M5 ;
        RECT  10.416 0 10.44 0.084 ;
    END
  END o[165]
  PIN o[166]
    DIRECTION OUTPUT ;
    USE SIGNAL ;
    PORT
      LAYER M5 ;
        RECT  10.512 0 10.536 0.084 ;
    END
  END o[166]
  PIN o[167]
    DIRECTION OUTPUT ;
    USE SIGNAL ;
    PORT
      LAYER M5 ;
        RECT  10.608 0 10.632 0.084 ;
    END
  END o[167]
  PIN o[168]
    DIRECTION OUTPUT ;
    USE SIGNAL ;
    PORT
      LAYER M5 ;
        RECT  10.704 0 10.728 0.084 ;
    END
  END o[168]
  PIN o[169]
    DIRECTION OUTPUT ;
    USE SIGNAL ;
    PORT
      LAYER M5 ;
        RECT  10.8 0 10.824 0.084 ;
    END
  END o[169]
  PIN o[16]
    DIRECTION OUTPUT ;
    USE SIGNAL ;
    PORT
      LAYER M5 ;
        RECT  5.328 0 5.352 0.084 ;
    END
  END o[16]
  PIN o[170]
    DIRECTION OUTPUT ;
    USE SIGNAL ;
    PORT
      LAYER M5 ;
        RECT  10.896 0 10.92 0.084 ;
    END
  END o[170]
  PIN o[171]
    DIRECTION OUTPUT ;
    USE SIGNAL ;
    PORT
      LAYER M5 ;
        RECT  10.992 0 11.016 0.084 ;
    END
  END o[171]
  PIN o[172]
    DIRECTION OUTPUT ;
    USE SIGNAL ;
    PORT
      LAYER M5 ;
        RECT  11.088 0 11.112 0.084 ;
    END
  END o[172]
  PIN o[173]
    DIRECTION OUTPUT ;
    USE SIGNAL ;
    PORT
      LAYER M5 ;
        RECT  11.184 0 11.208 0.084 ;
    END
  END o[173]
  PIN o[174]
    DIRECTION OUTPUT ;
    USE SIGNAL ;
    PORT
      LAYER M5 ;
        RECT  11.28 0 11.304 0.084 ;
    END
  END o[174]
  PIN o[175]
    DIRECTION OUTPUT ;
    USE SIGNAL ;
    PORT
      LAYER M5 ;
        RECT  11.376 0 11.4 0.084 ;
    END
  END o[175]
  PIN o[176]
    DIRECTION OUTPUT ;
    USE SIGNAL ;
    PORT
      LAYER M5 ;
        RECT  11.472 0 11.496 0.084 ;
    END
  END o[176]
  PIN o[177]
    DIRECTION OUTPUT ;
    USE SIGNAL ;
    PORT
      LAYER M5 ;
        RECT  11.568 0 11.592 0.084 ;
    END
  END o[177]
  PIN o[178]
    DIRECTION OUTPUT ;
    USE SIGNAL ;
    PORT
      LAYER M5 ;
        RECT  11.664 0 11.688 0.084 ;
    END
  END o[178]
  PIN o[179]
    DIRECTION OUTPUT ;
    USE SIGNAL ;
    PORT
      LAYER M5 ;
        RECT  11.76 0 11.784 0.084 ;
    END
  END o[179]
  PIN o[17]
    DIRECTION OUTPUT ;
    USE SIGNAL ;
    PORT
      LAYER M5 ;
        RECT  5.424 0 5.448 0.084 ;
    END
  END o[17]
  PIN o[180]
    DIRECTION OUTPUT ;
    USE SIGNAL ;
    PORT
      LAYER M5 ;
        RECT  11.856 0 11.88 0.084 ;
    END
  END o[180]
  PIN o[181]
    DIRECTION OUTPUT ;
    USE SIGNAL ;
    PORT
      LAYER M5 ;
        RECT  11.952 0 11.976 0.084 ;
    END
  END o[181]
  PIN o[182]
    DIRECTION OUTPUT ;
    USE SIGNAL ;
    PORT
      LAYER M5 ;
        RECT  12.048 0 12.072 0.084 ;
    END
  END o[182]
  PIN o[183]
    DIRECTION OUTPUT ;
    USE SIGNAL ;
    PORT
      LAYER M5 ;
        RECT  12.144 0 12.168 0.084 ;
    END
  END o[183]
  PIN o[184]
    DIRECTION OUTPUT ;
    USE SIGNAL ;
    PORT
      LAYER M5 ;
        RECT  12.24 0 12.264 0.084 ;
    END
  END o[184]
  PIN o[185]
    DIRECTION OUTPUT ;
    USE SIGNAL ;
    PORT
      LAYER M5 ;
        RECT  12.336 0 12.36 0.084 ;
    END
  END o[185]
  PIN o[186]
    DIRECTION OUTPUT ;
    USE SIGNAL ;
    PORT
      LAYER M5 ;
        RECT  12.432 0 12.456 0.084 ;
    END
  END o[186]
  PIN o[187]
    DIRECTION OUTPUT ;
    USE SIGNAL ;
    PORT
      LAYER M5 ;
        RECT  12.528 0 12.552 0.084 ;
    END
  END o[187]
  PIN o[188]
    DIRECTION OUTPUT ;
    USE SIGNAL ;
    PORT
      LAYER M5 ;
        RECT  12.624 0 12.648 0.084 ;
    END
  END o[188]
  PIN o[189]
    DIRECTION OUTPUT ;
    USE SIGNAL ;
    PORT
      LAYER M5 ;
        RECT  12.72 0 12.744 0.084 ;
    END
  END o[189]
  PIN o[18]
    DIRECTION OUTPUT ;
    USE SIGNAL ;
    PORT
      LAYER M5 ;
        RECT  5.52 0 5.544 0.084 ;
    END
  END o[18]
  PIN o[190]
    DIRECTION OUTPUT ;
    USE SIGNAL ;
    PORT
      LAYER M5 ;
        RECT  12.816 0 12.84 0.084 ;
    END
  END o[190]
  PIN o[191]
    DIRECTION OUTPUT ;
    USE SIGNAL ;
    PORT
      LAYER M5 ;
        RECT  12.912 0 12.936 0.084 ;
    END
  END o[191]
  PIN o[192]
    DIRECTION OUTPUT ;
    USE SIGNAL ;
    PORT
      LAYER M5 ;
        RECT  19.92 0 19.944 0.084 ;
    END
  END o[192]
  PIN o[193]
    DIRECTION OUTPUT ;
    USE SIGNAL ;
    PORT
      LAYER M5 ;
        RECT  20.016 0 20.04 0.084 ;
    END
  END o[193]
  PIN o[194]
    DIRECTION OUTPUT ;
    USE SIGNAL ;
    PORT
      LAYER M5 ;
        RECT  20.112 0 20.136 0.084 ;
    END
  END o[194]
  PIN o[195]
    DIRECTION OUTPUT ;
    USE SIGNAL ;
    PORT
      LAYER M5 ;
        RECT  20.208 0 20.232 0.084 ;
    END
  END o[195]
  PIN o[196]
    DIRECTION OUTPUT ;
    USE SIGNAL ;
    PORT
      LAYER M5 ;
        RECT  20.304 0 20.328 0.084 ;
    END
  END o[196]
  PIN o[197]
    DIRECTION OUTPUT ;
    USE SIGNAL ;
    PORT
      LAYER M5 ;
        RECT  20.4 0 20.424 0.084 ;
    END
  END o[197]
  PIN o[198]
    DIRECTION OUTPUT ;
    USE SIGNAL ;
    PORT
      LAYER M5 ;
        RECT  20.496 0 20.52 0.084 ;
    END
  END o[198]
  PIN o[199]
    DIRECTION OUTPUT ;
    USE SIGNAL ;
    PORT
      LAYER M5 ;
        RECT  20.592 0 20.616 0.084 ;
    END
  END o[199]
  PIN o[19]
    DIRECTION OUTPUT ;
    USE SIGNAL ;
    PORT
      LAYER M5 ;
        RECT  5.616 0 5.64 0.084 ;
    END
  END o[19]
  PIN o[1]
    DIRECTION OUTPUT ;
    USE SIGNAL ;
    PORT
      LAYER M5 ;
        RECT  3.888 0 3.912 0.084 ;
    END
  END o[1]
  PIN o[200]
    DIRECTION OUTPUT ;
    USE SIGNAL ;
    PORT
      LAYER M5 ;
        RECT  20.688 0 20.712 0.084 ;
    END
  END o[200]
  PIN o[201]
    DIRECTION OUTPUT ;
    USE SIGNAL ;
    PORT
      LAYER M5 ;
        RECT  20.784 0 20.808 0.084 ;
    END
  END o[201]
  PIN o[202]
    DIRECTION OUTPUT ;
    USE SIGNAL ;
    PORT
      LAYER M5 ;
        RECT  20.88 0 20.904 0.084 ;
    END
  END o[202]
  PIN o[203]
    DIRECTION OUTPUT ;
    USE SIGNAL ;
    PORT
      LAYER M5 ;
        RECT  20.976 0 21 0.084 ;
    END
  END o[203]
  PIN o[204]
    DIRECTION OUTPUT ;
    USE SIGNAL ;
    PORT
      LAYER M5 ;
        RECT  21.072 0 21.096 0.084 ;
    END
  END o[204]
  PIN o[205]
    DIRECTION OUTPUT ;
    USE SIGNAL ;
    PORT
      LAYER M5 ;
        RECT  21.168 0 21.192 0.084 ;
    END
  END o[205]
  PIN o[206]
    DIRECTION OUTPUT ;
    USE SIGNAL ;
    PORT
      LAYER M5 ;
        RECT  21.264 0 21.288 0.084 ;
    END
  END o[206]
  PIN o[207]
    DIRECTION OUTPUT ;
    USE SIGNAL ;
    PORT
      LAYER M5 ;
        RECT  21.36 0 21.384 0.084 ;
    END
  END o[207]
  PIN o[208]
    DIRECTION OUTPUT ;
    USE SIGNAL ;
    PORT
      LAYER M5 ;
        RECT  21.456 0 21.48 0.084 ;
    END
  END o[208]
  PIN o[209]
    DIRECTION OUTPUT ;
    USE SIGNAL ;
    PORT
      LAYER M5 ;
        RECT  21.552 0 21.576 0.084 ;
    END
  END o[209]
  PIN o[20]
    DIRECTION OUTPUT ;
    USE SIGNAL ;
    PORT
      LAYER M5 ;
        RECT  5.712 0 5.736 0.084 ;
    END
  END o[20]
  PIN o[210]
    DIRECTION OUTPUT ;
    USE SIGNAL ;
    PORT
      LAYER M5 ;
        RECT  21.648 0 21.672 0.084 ;
    END
  END o[210]
  PIN o[211]
    DIRECTION OUTPUT ;
    USE SIGNAL ;
    PORT
      LAYER M5 ;
        RECT  21.744 0 21.768 0.084 ;
    END
  END o[211]
  PIN o[212]
    DIRECTION OUTPUT ;
    USE SIGNAL ;
    PORT
      LAYER M5 ;
        RECT  21.84 0 21.864 0.084 ;
    END
  END o[212]
  PIN o[213]
    DIRECTION OUTPUT ;
    USE SIGNAL ;
    PORT
      LAYER M5 ;
        RECT  21.936 0 21.96 0.084 ;
    END
  END o[213]
  PIN o[21]
    DIRECTION OUTPUT ;
    USE SIGNAL ;
    PORT
      LAYER M5 ;
        RECT  5.808 0 5.832 0.084 ;
    END
  END o[21]
  PIN o[22]
    DIRECTION OUTPUT ;
    USE SIGNAL ;
    PORT
      LAYER M5 ;
        RECT  5.904 0 5.928 0.084 ;
    END
  END o[22]
  PIN o[23]
    DIRECTION OUTPUT ;
    USE SIGNAL ;
    PORT
      LAYER M5 ;
        RECT  6 0 6.024 0.084 ;
    END
  END o[23]
  PIN o[24]
    DIRECTION OUTPUT ;
    USE SIGNAL ;
    PORT
      LAYER M5 ;
        RECT  6.096 0 6.12 0.084 ;
    END
  END o[24]
  PIN o[25]
    DIRECTION OUTPUT ;
    USE SIGNAL ;
    PORT
      LAYER M5 ;
        RECT  6.192 0 6.216 0.084 ;
    END
  END o[25]
  PIN o[26]
    DIRECTION OUTPUT ;
    USE SIGNAL ;
    PORT
      LAYER M5 ;
        RECT  6.288 0 6.312 0.084 ;
    END
  END o[26]
  PIN o[27]
    DIRECTION OUTPUT ;
    USE SIGNAL ;
    PORT
      LAYER M5 ;
        RECT  6.384 0 6.408 0.084 ;
    END
  END o[27]
  PIN o[28]
    DIRECTION OUTPUT ;
    USE SIGNAL ;
    PORT
      LAYER M5 ;
        RECT  6.48 0 6.504 0.084 ;
    END
  END o[28]
  PIN o[29]
    DIRECTION OUTPUT ;
    USE SIGNAL ;
    PORT
      LAYER M5 ;
        RECT  6.576 0 6.6 0.084 ;
    END
  END o[29]
  PIN o[2]
    DIRECTION OUTPUT ;
    USE SIGNAL ;
    PORT
      LAYER M5 ;
        RECT  3.984 0 4.008 0.084 ;
    END
  END o[2]
  PIN o[30]
    DIRECTION OUTPUT ;
    USE SIGNAL ;
    PORT
      LAYER M5 ;
        RECT  6.672 0 6.696 0.084 ;
    END
  END o[30]
  PIN o[31]
    DIRECTION OUTPUT ;
    USE SIGNAL ;
    PORT
      LAYER M5 ;
        RECT  6.768 0 6.792 0.084 ;
    END
  END o[31]
  PIN o[32]
    DIRECTION OUTPUT ;
    USE SIGNAL ;
    PORT
      LAYER M5 ;
        RECT  6.864 0 6.888 0.084 ;
    END
  END o[32]
  PIN o[33]
    DIRECTION OUTPUT ;
    USE SIGNAL ;
    PORT
      LAYER M5 ;
        RECT  6.96 0 6.984 0.084 ;
    END
  END o[33]
  PIN o[34]
    DIRECTION OUTPUT ;
    USE SIGNAL ;
    PORT
      LAYER M5 ;
        RECT  7.056 0 7.08 0.084 ;
    END
  END o[34]
  PIN o[35]
    DIRECTION OUTPUT ;
    USE SIGNAL ;
    PORT
      LAYER M5 ;
        RECT  7.152 0 7.176 0.084 ;
    END
  END o[35]
  PIN o[36]
    DIRECTION OUTPUT ;
    USE SIGNAL ;
    PORT
      LAYER M5 ;
        RECT  7.248 0 7.272 0.084 ;
    END
  END o[36]
  PIN o[37]
    DIRECTION OUTPUT ;
    USE SIGNAL ;
    PORT
      LAYER M5 ;
        RECT  7.344 0 7.368 0.084 ;
    END
  END o[37]
  PIN o[38]
    DIRECTION OUTPUT ;
    USE SIGNAL ;
    PORT
      LAYER M5 ;
        RECT  7.44 0 7.464 0.084 ;
    END
  END o[38]
  PIN o[39]
    DIRECTION OUTPUT ;
    USE SIGNAL ;
    PORT
      LAYER M5 ;
        RECT  7.536 0 7.56 0.084 ;
    END
  END o[39]
  PIN o[3]
    DIRECTION OUTPUT ;
    USE SIGNAL ;
    PORT
      LAYER M5 ;
        RECT  4.08 0 4.104 0.084 ;
    END
  END o[3]
  PIN o[40]
    DIRECTION OUTPUT ;
    USE SIGNAL ;
    PORT
      LAYER M5 ;
        RECT  7.632 0 7.656 0.084 ;
    END
  END o[40]
  PIN o[41]
    DIRECTION OUTPUT ;
    USE SIGNAL ;
    PORT
      LAYER M5 ;
        RECT  7.728 0 7.752 0.084 ;
    END
  END o[41]
  PIN o[42]
    DIRECTION OUTPUT ;
    USE SIGNAL ;
    PORT
      LAYER M5 ;
        RECT  7.824 0 7.848 0.084 ;
    END
  END o[42]
  PIN o[43]
    DIRECTION OUTPUT ;
    USE SIGNAL ;
    PORT
      LAYER M5 ;
        RECT  7.92 0 7.944 0.084 ;
    END
  END o[43]
  PIN o[44]
    DIRECTION OUTPUT ;
    USE SIGNAL ;
    PORT
      LAYER M5 ;
        RECT  8.016 0 8.04 0.084 ;
    END
  END o[44]
  PIN o[45]
    DIRECTION OUTPUT ;
    USE SIGNAL ;
    PORT
      LAYER M5 ;
        RECT  8.112 0 8.136 0.084 ;
    END
  END o[45]
  PIN o[46]
    DIRECTION OUTPUT ;
    USE SIGNAL ;
    PORT
      LAYER M5 ;
        RECT  8.208 0 8.232 0.084 ;
    END
  END o[46]
  PIN o[47]
    DIRECTION OUTPUT ;
    USE SIGNAL ;
    PORT
      LAYER M5 ;
        RECT  8.304 0 8.328 0.084 ;
    END
  END o[47]
  PIN o[48]
    DIRECTION OUTPUT ;
    USE SIGNAL ;
    PORT
      LAYER M5 ;
        RECT  8.4 0 8.424 0.084 ;
    END
  END o[48]
  PIN o[49]
    DIRECTION OUTPUT ;
    USE SIGNAL ;
    PORT
      LAYER M5 ;
        RECT  8.496 0 8.52 0.084 ;
    END
  END o[49]
  PIN o[4]
    DIRECTION OUTPUT ;
    USE SIGNAL ;
    PORT
      LAYER M5 ;
        RECT  4.176 0 4.2 0.084 ;
    END
  END o[4]
  PIN o[50]
    DIRECTION OUTPUT ;
    USE SIGNAL ;
    PORT
      LAYER M5 ;
        RECT  8.592 0 8.616 0.084 ;
    END
  END o[50]
  PIN o[51]
    DIRECTION OUTPUT ;
    USE SIGNAL ;
    PORT
      LAYER M5 ;
        RECT  8.688 0 8.712 0.084 ;
    END
  END o[51]
  PIN o[52]
    DIRECTION OUTPUT ;
    USE SIGNAL ;
    PORT
      LAYER M5 ;
        RECT  8.784 0 8.808 0.084 ;
    END
  END o[52]
  PIN o[53]
    DIRECTION OUTPUT ;
    USE SIGNAL ;
    PORT
      LAYER M5 ;
        RECT  8.88 0 8.904 0.084 ;
    END
  END o[53]
  PIN o[54]
    DIRECTION OUTPUT ;
    USE SIGNAL ;
    PORT
      LAYER M5 ;
        RECT  8.976 0 9 0.084 ;
    END
  END o[54]
  PIN o[55]
    DIRECTION OUTPUT ;
    USE SIGNAL ;
    PORT
      LAYER M5 ;
        RECT  9.072 0 9.096 0.084 ;
    END
  END o[55]
  PIN o[56]
    DIRECTION OUTPUT ;
    USE SIGNAL ;
    PORT
      LAYER M5 ;
        RECT  9.168 0 9.192 0.084 ;
    END
  END o[56]
  PIN o[57]
    DIRECTION OUTPUT ;
    USE SIGNAL ;
    PORT
      LAYER M5 ;
        RECT  9.264 0 9.288 0.084 ;
    END
  END o[57]
  PIN o[58]
    DIRECTION OUTPUT ;
    USE SIGNAL ;
    PORT
      LAYER M5 ;
        RECT  9.36 0 9.384 0.084 ;
    END
  END o[58]
  PIN o[59]
    DIRECTION OUTPUT ;
    USE SIGNAL ;
    PORT
      LAYER M5 ;
        RECT  9.456 0 9.48 0.084 ;
    END
  END o[59]
  PIN o[5]
    DIRECTION OUTPUT ;
    USE SIGNAL ;
    PORT
      LAYER M5 ;
        RECT  4.272 0 4.296 0.084 ;
    END
  END o[5]
  PIN o[60]
    DIRECTION OUTPUT ;
    USE SIGNAL ;
    PORT
      LAYER M5 ;
        RECT  9.552 0 9.576 0.084 ;
    END
  END o[60]
  PIN o[61]
    DIRECTION OUTPUT ;
    USE SIGNAL ;
    PORT
      LAYER M5 ;
        RECT  9.648 0 9.672 0.084 ;
    END
  END o[61]
  PIN o[62]
    DIRECTION OUTPUT ;
    USE SIGNAL ;
    PORT
      LAYER M5 ;
        RECT  9.744 0 9.768 0.084 ;
    END
  END o[62]
  PIN o[63]
    DIRECTION OUTPUT ;
    USE SIGNAL ;
    PORT
      LAYER M5 ;
        RECT  9.84 0 9.864 0.084 ;
    END
  END o[63]
  PIN o[64]
    DIRECTION OUTPUT ;
    USE SIGNAL ;
    PORT
      LAYER M5 ;
        RECT  0.72 0 0.744 0.084 ;
    END
  END o[64]
  PIN o[65]
    DIRECTION OUTPUT ;
    USE SIGNAL ;
    PORT
      LAYER M5 ;
        RECT  0.816 0 0.84 0.084 ;
    END
  END o[65]
  PIN o[66]
    DIRECTION OUTPUT ;
    USE SIGNAL ;
    PORT
      LAYER M5 ;
        RECT  0.912 0 0.936 0.084 ;
    END
  END o[66]
  PIN o[67]
    DIRECTION OUTPUT ;
    USE SIGNAL ;
    PORT
      LAYER M5 ;
        RECT  1.008 0 1.032 0.084 ;
    END
  END o[67]
  PIN o[68]
    DIRECTION OUTPUT ;
    USE SIGNAL ;
    PORT
      LAYER M5 ;
        RECT  1.104 0 1.128 0.084 ;
    END
  END o[68]
  PIN o[69]
    DIRECTION OUTPUT ;
    USE SIGNAL ;
    PORT
      LAYER M5 ;
        RECT  1.2 0 1.224 0.084 ;
    END
  END o[69]
  PIN o[6]
    DIRECTION OUTPUT ;
    USE SIGNAL ;
    PORT
      LAYER M5 ;
        RECT  4.368 0 4.392 0.084 ;
    END
  END o[6]
  PIN o[70]
    DIRECTION OUTPUT ;
    USE SIGNAL ;
    PORT
      LAYER M5 ;
        RECT  1.296 0 1.32 0.084 ;
    END
  END o[70]
  PIN o[71]
    DIRECTION OUTPUT ;
    USE SIGNAL ;
    PORT
      LAYER M5 ;
        RECT  1.392 0 1.416 0.084 ;
    END
  END o[71]
  PIN o[72]
    DIRECTION OUTPUT ;
    USE SIGNAL ;
    PORT
      LAYER M5 ;
        RECT  1.488 0 1.512 0.084 ;
    END
  END o[72]
  PIN o[73]
    DIRECTION OUTPUT ;
    USE SIGNAL ;
    PORT
      LAYER M5 ;
        RECT  1.584 0 1.608 0.084 ;
    END
  END o[73]
  PIN o[74]
    DIRECTION OUTPUT ;
    USE SIGNAL ;
    PORT
      LAYER M5 ;
        RECT  1.68 0 1.704 0.084 ;
    END
  END o[74]
  PIN o[75]
    DIRECTION OUTPUT ;
    USE SIGNAL ;
    PORT
      LAYER M5 ;
        RECT  1.776 0 1.8 0.084 ;
    END
  END o[75]
  PIN o[76]
    DIRECTION OUTPUT ;
    USE SIGNAL ;
    PORT
      LAYER M5 ;
        RECT  1.872 0 1.896 0.084 ;
    END
  END o[76]
  PIN o[77]
    DIRECTION OUTPUT ;
    USE SIGNAL ;
    PORT
      LAYER M5 ;
        RECT  1.968 0 1.992 0.084 ;
    END
  END o[77]
  PIN o[78]
    DIRECTION OUTPUT ;
    USE SIGNAL ;
    PORT
      LAYER M5 ;
        RECT  2.064 0 2.088 0.084 ;
    END
  END o[78]
  PIN o[79]
    DIRECTION OUTPUT ;
    USE SIGNAL ;
    PORT
      LAYER M5 ;
        RECT  2.16 0 2.184 0.084 ;
    END
  END o[79]
  PIN o[7]
    DIRECTION OUTPUT ;
    USE SIGNAL ;
    PORT
      LAYER M5 ;
        RECT  4.464 0 4.488 0.084 ;
    END
  END o[7]
  PIN o[80]
    DIRECTION OUTPUT ;
    USE SIGNAL ;
    PORT
      LAYER M5 ;
        RECT  2.256 0 2.28 0.084 ;
    END
  END o[80]
  PIN o[81]
    DIRECTION OUTPUT ;
    USE SIGNAL ;
    PORT
      LAYER M5 ;
        RECT  2.352 0 2.376 0.084 ;
    END
  END o[81]
  PIN o[82]
    DIRECTION OUTPUT ;
    USE SIGNAL ;
    PORT
      LAYER M5 ;
        RECT  2.448 0 2.472 0.084 ;
    END
  END o[82]
  PIN o[83]
    DIRECTION OUTPUT ;
    USE SIGNAL ;
    PORT
      LAYER M5 ;
        RECT  2.544 0 2.568 0.084 ;
    END
  END o[83]
  PIN o[84]
    DIRECTION OUTPUT ;
    USE SIGNAL ;
    PORT
      LAYER M5 ;
        RECT  2.64 0 2.664 0.084 ;
    END
  END o[84]
  PIN o[85]
    DIRECTION OUTPUT ;
    USE SIGNAL ;
    PORT
      LAYER M5 ;
        RECT  2.736 0 2.76 0.084 ;
    END
  END o[85]
  PIN o[86]
    DIRECTION OUTPUT ;
    USE SIGNAL ;
    PORT
      LAYER M5 ;
        RECT  2.832 0 2.856 0.084 ;
    END
  END o[86]
  PIN o[87]
    DIRECTION OUTPUT ;
    USE SIGNAL ;
    PORT
      LAYER M5 ;
        RECT  2.928 0 2.952 0.084 ;
    END
  END o[87]
  PIN o[88]
    DIRECTION OUTPUT ;
    USE SIGNAL ;
    PORT
      LAYER M5 ;
        RECT  3.024 0 3.048 0.084 ;
    END
  END o[88]
  PIN o[89]
    DIRECTION OUTPUT ;
    USE SIGNAL ;
    PORT
      LAYER M5 ;
        RECT  3.12 0 3.144 0.084 ;
    END
  END o[89]
  PIN o[8]
    DIRECTION OUTPUT ;
    USE SIGNAL ;
    PORT
      LAYER M5 ;
        RECT  4.56 0 4.584 0.084 ;
    END
  END o[8]
  PIN o[90]
    DIRECTION OUTPUT ;
    USE SIGNAL ;
    PORT
      LAYER M5 ;
        RECT  3.216 0 3.24 0.084 ;
    END
  END o[90]
  PIN o[91]
    DIRECTION OUTPUT ;
    USE SIGNAL ;
    PORT
      LAYER M5 ;
        RECT  3.312 0 3.336 0.084 ;
    END
  END o[91]
  PIN o[92]
    DIRECTION OUTPUT ;
    USE SIGNAL ;
    PORT
      LAYER M5 ;
        RECT  3.408 0 3.432 0.084 ;
    END
  END o[92]
  PIN o[93]
    DIRECTION OUTPUT ;
    USE SIGNAL ;
    PORT
      LAYER M5 ;
        RECT  3.504 0 3.528 0.084 ;
    END
  END o[93]
  PIN o[94]
    DIRECTION OUTPUT ;
    USE SIGNAL ;
    PORT
      LAYER M5 ;
        RECT  3.6 0 3.624 0.084 ;
    END
  END o[94]
  PIN o[95]
    DIRECTION OUTPUT ;
    USE SIGNAL ;
    PORT
      LAYER M5 ;
        RECT  3.696 0 3.72 0.084 ;
    END
  END o[95]
  PIN o[96]
    DIRECTION OUTPUT ;
    USE SIGNAL ;
    PORT
      LAYER M5 ;
        RECT  13.008 0 13.032 0.084 ;
    END
  END o[96]
  PIN o[97]
    DIRECTION OUTPUT ;
    USE SIGNAL ;
    PORT
      LAYER M5 ;
        RECT  13.104 0 13.128 0.084 ;
    END
  END o[97]
  PIN o[98]
    DIRECTION OUTPUT ;
    USE SIGNAL ;
    PORT
      LAYER M5 ;
        RECT  13.2 0 13.224 0.084 ;
    END
  END o[98]
  PIN o[99]
    DIRECTION OUTPUT ;
    USE SIGNAL ;
    PORT
      LAYER M5 ;
        RECT  13.296 0 13.32 0.084 ;
    END
  END o[99]
  PIN o[9]
    DIRECTION OUTPUT ;
    USE SIGNAL ;
    PORT
      LAYER M5 ;
        RECT  4.656 0 4.68 0.084 ;
    END
  END o[9]
  PIN rs
    DIRECTION INPUT ;
    USE SIGNAL ;
    PORT
      LAYER M4 ;
        RECT  34.476 3.12 34.56 3.144 ;
    END
  END rs
  PIN VDD
    DIRECTION INOUT ;
    USE POWER ;
    PORT
      LAYER M5 ;
        RECT  29.592 2.151 29.712 17.289 ;
        RECT  24.192 2.151 24.312 17.289 ;
        RECT  18.792 2.151 18.912 17.289 ;
        RECT  13.392 2.151 13.512 17.289 ;
        RECT  7.992 2.151 8.112 17.289 ;
        RECT  2.592 2.151 2.712 17.289 ;
    END
  END VDD
  PIN VSS
    DIRECTION INOUT ;
    USE GROUND ;
    PORT
      LAYER M5 ;
        RECT  29.4 2.137 29.52 17.303 ;
        RECT  24 2.137 24.12 17.303 ;
        RECT  18.6 2.137 18.72 17.303 ;
        RECT  13.2 2.137 13.32 17.303 ;
        RECT  7.8 2.137 7.92 17.303 ;
        RECT  2.4 2.137 2.52 17.303 ;
    END
  END VSS
  # OT_OBS_CLOSED layer=M5 d_um=1.536 added=73
  OBS
    LAYER RVTN ;
     RECT  2.16 2.16 32.4 2.295 ;
     RECT  2.16 2.565 32.4 2.835 ;
     RECT  2.16 3.105 32.4 3.375 ;
     RECT  2.16 3.645 32.4 3.915 ;
     RECT  2.16 4.185 32.4 4.455 ;
     RECT  2.16 4.725 32.4 4.995 ;
     RECT  2.16 5.265 32.4 5.535 ;
     RECT  2.16 5.805 32.4 6.075 ;
     RECT  2.16 6.345 32.4 6.615 ;
     RECT  2.16 6.885 32.4 7.155 ;
     RECT  2.16 7.425 32.4 7.695 ;
     RECT  2.16 7.965 32.4 8.235 ;
     RECT  2.16 8.505 32.4 8.775 ;
     RECT  2.16 9.045 32.4 9.315 ;
     RECT  2.16 9.585 32.4 9.855 ;
     RECT  2.16 10.125 32.4 10.395 ;
     RECT  2.16 10.665 32.4 10.935 ;
     RECT  2.16 11.205 32.4 11.475 ;
     RECT  2.16 11.745 32.4 12.015 ;
     RECT  2.16 12.285 32.4 12.555 ;
     RECT  2.16 12.825 32.4 13.095 ;
     RECT  2.16 13.365 32.4 13.635 ;
     RECT  2.16 13.905 32.4 14.175 ;
     RECT  2.16 14.445 32.4 14.715 ;
     RECT  2.16 14.985 32.4 15.255 ;
     RECT  2.16 15.525 32.4 15.795 ;
     RECT  2.16 16.065 32.4 16.335 ;
     RECT  2.16 16.605 32.4 16.875 ;
     RECT  2.16 17.145 32.4 17.28 ;
    LAYER RVTP ;
     RECT  2.16 2.295 32.4 2.565 ;
     RECT  2.16 2.835 32.4 3.105 ;
     RECT  2.16 3.375 32.4 3.645 ;
     RECT  2.16 3.915 32.4 4.185 ;
     RECT  2.16 4.455 32.4 4.725 ;
     RECT  2.16 4.995 32.4 5.265 ;
     RECT  2.16 5.535 32.4 5.805 ;
     RECT  2.16 6.075 32.4 6.345 ;
     RECT  2.16 6.615 32.4 6.885 ;
     RECT  2.16 7.155 32.4 7.425 ;
     RECT  2.16 7.695 32.4 7.965 ;
     RECT  2.16 8.235 32.4 8.505 ;
     RECT  2.16 8.775 32.4 9.045 ;
     RECT  2.16 9.315 32.4 9.585 ;
     RECT  2.16 9.855 32.4 10.125 ;
     RECT  2.16 10.395 32.4 10.665 ;
     RECT  2.16 10.935 32.4 11.205 ;
     RECT  2.16 11.475 32.4 11.745 ;
     RECT  2.16 12.015 32.4 12.285 ;
     RECT  2.16 12.555 32.4 12.825 ;
     RECT  2.16 13.095 32.4 13.365 ;
     RECT  2.16 13.635 32.4 13.905 ;
     RECT  2.16 14.175 32.4 14.445 ;
     RECT  2.16 14.715 32.4 14.985 ;
     RECT  2.16 15.255 32.4 15.525 ;
     RECT  2.16 15.795 32.4 16.065 ;
     RECT  2.16 16.335 32.4 16.605 ;
     RECT  2.16 16.875 32.4 17.145 ;
    LAYER M1 ;
     RECT  2.16 2.151 32.4 17.289 ;
    LAYER M2 ;
     RECT  1.687 6.966 1.723 6.984 ;
     RECT  1.723 6.966 1.759 7.182 ;
     RECT  1.759 6.624 1.903 7.182 ;
     RECT  1.939 2.61 2.011 2.628 ;
     RECT  1.939 8.136 2.011 8.154 ;
     RECT  2.011 2.61 2.047 2.934 ;
     RECT  2.047 2.232 2.119 2.934 ;
     RECT  2.083 9.396 2.155 9.414 ;
     RECT  2.119 2.232 2.16 3.096 ;
     RECT  2.155 3.96 2.16 3.978 ;
     RECT  1.903 6.156 2.16 7.182 ;
     RECT  2.011 8.136 2.16 8.262 ;
     RECT  2.155 9.126 2.16 9.414 ;
     RECT  1.903 15.336 2.16 15.354 ;
     RECT  2.16 2.151 4.675 17.289 ;
     RECT  4.675 2.034 5.999 17.289 ;
     RECT  5.999 2.106 7.691 17.289 ;
     RECT  7.691 2.151 8.887 17.289 ;
     RECT  8.887 2.106 10.615 17.289 ;
     RECT  10.615 2.07 11.039 17.289 ;
     RECT  12.199 1.152 12.299 1.17 ;
     RECT  11.039 2.106 14.719 17.289 ;
     RECT  14.719 2.07 15.583 17.289 ;
     RECT  15.583 2.034 17.095 17.289 ;
     RECT  17.923 18.774 18.095 18.792 ;
     RECT  19.399 0.846 19.939 0.864 ;
     RECT  17.095 1.926 19.939 17.289 ;
     RECT  19.939 0.846 25.691 17.289 ;
     RECT  25.691 0.846 26.303 0.864 ;
     RECT  25.691 1.998 28.967 17.289 ;
     RECT  28.967 2.151 32.4 17.289 ;
     RECT  32.4 4.662 33.071 4.68 ;
    LAYER M3 ;
     RECT  2.376 0.043 2.394 0.091 ;
     RECT  3.996 0.043 4.014 0.091 ;
     RECT  20.808 0.043 20.826 0.091 ;
     RECT  4.896 0.091 5.382 0.139 ;
     RECT  9.288 0.091 9.306 0.139 ;
     RECT  14.076 0.091 14.094 0.139 ;
     RECT  19.404 0.091 19.422 0.139 ;
     RECT  24.984 0.091 25.002 0.139 ;
     RECT  2.376 0.091 4.014 0.173 ;
     RECT  12.276 0.091 12.294 0.187 ;
     RECT  20.808 0.091 21.222 0.269 ;
     RECT  9.288 0.139 9.522 0.523 ;
     RECT  10.692 0.091 10.71 0.523 ;
     RECT  13.752 0.139 14.166 0.523 ;
     RECT  21.096 0.269 21.222 0.523 ;
     RECT  3.06 0.173 4.014 0.571 ;
     RECT  4.896 0.139 5.562 0.571 ;
     RECT  6.66 0.091 6.678 0.571 ;
     RECT  19.404 0.139 19.962 0.571 ;
     RECT  28.224 0.043 28.242 0.859 ;
     RECT  29.016 0.811 29.034 0.859 ;
     RECT  19.116 0.571 19.962 0.869 ;
     RECT  27.36 0.907 27.378 1.003 ;
     RECT  28.224 0.859 29.034 1.003 ;
     RECT  26.28 0.841 26.298 1.051 ;
     RECT  27.36 1.003 29.034 1.051 ;
     RECT  9.288 0.523 10.71 1.147 ;
     RECT  12.276 0.187 12.33 1.147 ;
     RECT  15.012 0.091 15.318 1.147 ;
     RECT  16.128 0.091 17.442 1.147 ;
     RECT  22.14 0.571 22.158 1.147 ;
     RECT  24.984 0.139 25.434 1.417 ;
     RECT  26.28 1.051 29.034 1.417 ;
     RECT  19.944 0.869 19.962 1.445 ;
     RECT  9 1.147 10.71 1.675 ;
     RECT  3.06 0.571 6.75 1.723 ;
     RECT  8.208 1.675 8.226 1.723 ;
     RECT  8.964 1.675 10.71 1.723 ;
     RECT  12.204 1.147 12.33 1.723 ;
     RECT  13.572 0.523 14.274 1.723 ;
     RECT  15.012 1.147 17.442 1.723 ;
     RECT  21.096 0.523 21.402 1.771 ;
     RECT  22.14 1.147 22.194 1.771 ;
     RECT  2.808 1.723 14.274 1.819 ;
     RECT  21.096 1.771 22.698 1.876 ;
     RECT  23.904 1.723 23.922 1.876 ;
     RECT  24.984 1.417 29.034 2.029 ;
     RECT  2.772 1.819 14.274 2.065 ;
     RECT  15.012 1.723 17.766 2.065 ;
     RECT  19.116 0.869 19.134 2.065 ;
     RECT  19.116 2.065 19.926 2.101 ;
     RECT  2.772 2.065 17.766 2.143 ;
     RECT  18.9 2.101 19.926 2.143 ;
     RECT  20.7 1.876 23.922 2.143 ;
     RECT  24.912 2.029 29.034 2.143 ;
     RECT  2.415 2.143 17.766 2.191 ;
     RECT  18.615 2.143 19.926 2.191 ;
     RECT  20.7 2.143 24.105 2.191 ;
     RECT  2.232 2.191 17.766 2.227 ;
     RECT  18.615 2.191 24.105 2.227 ;
     RECT  2.052 2.227 24.105 2.413 ;
     RECT  24.912 2.143 29.505 2.413 ;
     RECT  30.384 1.387 30.402 2.413 ;
     RECT  2.052 2.413 30.402 2.605 ;
     RECT  1.944 2.605 30.402 3.335 ;
     RECT  1.944 3.335 26.55 3.569 ;
     RECT  1.944 3.569 26.478 4.531 ;
     RECT  27.288 3.335 30.402 4.531 ;
     RECT  33.048 3.115 33.066 4.685 ;
     RECT  1.944 4.531 30.402 5.189 ;
     RECT  1.944 5.189 30.294 5.707 ;
     RECT  1.764 5.707 30.294 5.755 ;
     RECT  31.356 4.801 31.374 5.765 ;
     RECT  1.692 5.755 30.294 6.349 ;
     RECT  1.692 6.349 30.33 6.989 ;
     RECT  1.728 6.989 30.33 7.187 ;
     RECT  1.908 7.187 30.33 7.627 ;
     RECT  1.908 7.627 30.654 10.435 ;
     RECT  1.908 10.435 30.87 10.471 ;
     RECT  1.908 10.471 31.302 10.769 ;
     RECT  1.908 10.769 30.87 11.129 ;
     RECT  1.908 11.129 30.654 12.451 ;
     RECT  1.908 12.451 31.014 12.991 ;
     RECT  1.908 12.991 31.446 14.639 ;
     RECT  6.048 14.639 31.446 14.719 ;
     RECT  6.048 14.719 31.734 14.909 ;
     RECT  1.908 14.639 5.13 15.359 ;
     RECT  2.415 15.359 5.13 15.601 ;
     RECT  6.048 14.909 31.626 15.601 ;
     RECT  2.415 15.601 31.626 15.869 ;
     RECT  2.415 15.869 4.086 16.565 ;
     RECT  3.672 16.565 4.086 16.601 ;
     RECT  3.96 16.601 4.086 16.795 ;
     RECT  4.968 15.869 31.626 16.795 ;
     RECT  3.96 16.795 31.626 16.799 ;
     RECT  3.96 16.799 5.13 16.835 ;
     RECT  4.284 16.835 5.13 16.871 ;
     RECT  4.464 16.871 5.13 16.907 ;
     RECT  6.264 16.799 31.05 16.907 ;
     RECT  6.264 16.907 8.262 16.943 ;
     RECT  9.252 16.907 31.05 16.943 ;
     RECT  6.372 16.943 8.226 16.979 ;
     RECT  6.372 16.979 8.097 17.027 ;
     RECT  4.464 16.907 5.094 17.069 ;
     RECT  6.372 17.027 7.905 17.069 ;
     RECT  6.372 17.069 6.426 17.078 ;
     RECT  7.236 17.069 7.905 17.105 ;
     RECT  6.408 17.078 6.426 17.117 ;
     RECT  2.415 16.565 2.862 17.177 ;
     RECT  9.252 16.943 30.726 17.177 ;
     RECT  5.076 17.069 5.094 17.213 ;
     RECT  7.416 17.105 7.905 17.213 ;
     RECT  16.668 17.177 30.726 17.213 ;
     RECT  9.252 17.177 15.498 17.249 ;
     RECT  16.668 17.213 22.014 17.249 ;
     RECT  16.668 17.249 21.618 17.261 ;
     RECT  23.328 17.213 30.726 17.261 ;
     RECT  2.415 17.177 2.505 17.297 ;
     RECT  7.815 17.213 7.905 17.297 ;
     RECT  26.388 17.261 30.726 17.309 ;
     RECT  23.976 17.261 25.47 17.453 ;
     RECT  9.324 17.249 15.498 17.501 ;
     RECT  24.372 17.453 25.47 17.501 ;
     RECT  9.324 17.501 14.526 17.645 ;
     RECT  16.668 17.261 20.394 17.645 ;
     RECT  24.876 17.501 25.47 17.645 ;
     RECT  26.748 17.309 30.726 17.645 ;
     RECT  9.324 17.645 14.166 17.693 ;
     RECT  25.452 17.645 25.47 17.693 ;
     RECT  26.964 17.645 30.726 17.693 ;
     RECT  27.144 17.693 30.726 17.741 ;
     RECT  9.324 17.693 12.366 17.933 ;
     RECT  9.324 17.933 10.026 17.981 ;
     RECT  10.008 17.981 10.026 18.029 ;
     RECT  10.836 17.933 12.366 18.077 ;
     RECT  10.908 18.077 12.366 18.125 ;
     RECT  17.928 17.645 20.358 18.173 ;
     RECT  27.144 17.741 29.754 18.173 ;
     RECT  11.16 18.125 12.366 18.221 ;
     RECT  13.104 17.693 13.698 18.221 ;
     RECT  17.928 18.173 19.71 18.221 ;
     RECT  27.9 18.173 29.754 18.221 ;
     RECT  13.68 18.221 13.698 18.269 ;
     RECT  15.48 17.501 15.498 18.269 ;
     RECT  27.144 18.173 27.162 18.269 ;
     RECT  11.16 18.221 11.214 18.509 ;
     RECT  11.988 18.221 12.366 18.557 ;
     RECT  16.668 17.645 17.118 18.797 ;
     RECT  17.928 18.221 19.17 18.797 ;
     RECT  21.6 17.261 21.618 18.797 ;
     RECT  24.48 18.571 24.498 18.797 ;
     RECT  12.348 18.557 12.366 18.811 ;
     RECT  12.348 18.811 12.762 18.845 ;
     RECT  18.072 18.797 19.17 18.845 ;
     RECT  28.008 18.221 29.754 18.845 ;
     RECT  16.668 18.797 17.01 18.893 ;
     RECT  28.908 18.845 29.142 18.893 ;
     RECT  12.744 18.845 12.762 18.941 ;
     RECT  16.992 18.893 17.01 18.941 ;
     RECT  29.124 18.893 29.142 18.941 ;
     RECT  18.072 18.845 18.774 19.277 ;
     RECT  18.072 19.277 18.09 19.325 ;
     RECT  28.008 18.845 28.026 19.325 ;
     RECT  30.708 17.741 30.726 19.325 ;
     RECT  11.196 18.509 11.214 19.421 ;
     RECT  16.056 19.291 16.074 19.421 ;
    LAYER M4 ;
     RECT  0.709 7.344 0.805 7.368 ;
     RECT  0.805 7.104 0.997 7.368 ;
     RECT  0.997 6.288 1.189 7.368 ;
     RECT  1.189 5.712 1.381 7.368 ;
     RECT  1.477 9.264 1.765 9.288 ;
     RECT  1.285 10.32 1.765 10.344 ;
     RECT  1.381 5.712 1.861 7.656 ;
     RECT  1.765 9.264 1.861 10.344 ;
     RECT  2.293 0.24 2.321 0.264 ;
     RECT  2.321 0.144 2.365 0.264 ;
     RECT  0.901 4.704 2.408 4.728 ;
     RECT  1.861 5.712 2.408 10.344 ;
     RECT  2.329 12.48 2.408 12.504 ;
     RECT  2.365 0.048 2.483 0.264 ;
     RECT  2.408 2.148 2.512 17.292 ;
     RECT  2.512 2.148 2.629 17.022 ;
     RECT  2.629 1.728 2.704 17.022 ;
     RECT  2.483 0.048 2.819 0.168 ;
     RECT  2.704 12.48 2.877 13.656 ;
     RECT  2.877 12.528 2.963 13.656 ;
     RECT  2.704 1.728 3.593 9.288 ;
     RECT  2.704 14.88 3.805 14.904 ;
     RECT  3.805 14.88 3.877 15 ;
     RECT  2.704 16.224 3.877 16.584 ;
     RECT  2.704 10.32 3.881 11.016 ;
     RECT  2.963 12.72 4.019 13.656 ;
     RECT  2.819 0.048 4.025 0.12 ;
     RECT  3.593 1.728 4.115 9.144 ;
     RECT  4.019 12.72 4.169 13.08 ;
     RECT  3.877 14.88 4.261 16.584 ;
     RECT  4.261 14.112 4.268 16.584 ;
     RECT  4.268 14.112 4.355 16.824 ;
     RECT  4.115 1.728 4.457 8.568 ;
     RECT  4.355 14.112 4.493 16.296 ;
     RECT  4.025 0.096 4.517 0.12 ;
     RECT  4.517 0.096 4.601 0.6 ;
     RECT  4.457 2.88 4.673 8.568 ;
     RECT  3.881 10.32 4.709 10.344 ;
     RECT  4.7 11.76 4.787 11.784 ;
     RECT  4.493 14.112 4.961 14.76 ;
     RECT  4.673 2.88 5.033 7.896 ;
     RECT  4.601 0.096 5.393 0.168 ;
     RECT  5.393 0.144 5.573 0.168 ;
     RECT  5.033 2.88 5.573 7.752 ;
     RECT  4.457 1.728 5.701 1.848 ;
     RECT  5.573 2.88 5.701 6.552 ;
     RECT  4.169 12.768 5.785 13.08 ;
     RECT  4.961 14.112 5.785 14.376 ;
     RECT  5.701 1.728 5.797 6.552 ;
     RECT  5.797 1.152 5.933 6.552 ;
     RECT  5.933 1.152 5.989 6.36 ;
     RECT  5.785 12.768 6.181 14.376 ;
     RECT  4.493 15.84 6.181 16.296 ;
     RECT  6.181 12.768 6.217 16.296 ;
     RECT  5.989 0.576 6.221 6.36 ;
     RECT  6.217 12.768 6.325 16.44 ;
     RECT  6.325 12.768 6.361 16.68 ;
     RECT  6.361 12.768 6.397 16.92 ;
     RECT  6.397 12.768 6.613 17.112 ;
     RECT  6.221 0.576 6.649 6.072 ;
     RECT  6.649 0.096 6.725 6.072 ;
     RECT  5.573 7.632 6.725 7.752 ;
     RECT  6.725 0.096 6.733 0.6 ;
     RECT  6.733 0.144 6.761 0.6 ;
     RECT  6.901 10.128 7.729 10.152 ;
     RECT  6.725 1.728 7.808 6.072 ;
     RECT  6.725 7.728 7.808 7.752 ;
     RECT  7.729 10.128 7.808 10.92 ;
     RECT  6.613 11.952 7.808 17.112 ;
     RECT  6.761 0.144 7.859 0.168 ;
     RECT  7.808 1.728 7.912 17.292 ;
     RECT  7.912 1.728 8.005 17.022 ;
     RECT  8.005 1.68 8.104 17.022 ;
     RECT  8.104 11.952 8.129 16.872 ;
     RECT  8.129 12 8.237 16.872 ;
     RECT  8.237 12 8.273 16.68 ;
     RECT  8.104 1.68 8.381 6.744 ;
     RECT  8.381 1.68 8.869 5.208 ;
     RECT  8.104 7.728 9.097 8.76 ;
     RECT  8.104 9.792 9.097 10.92 ;
     RECT  9.097 7.728 9.205 10.92 ;
     RECT  8.273 12 9.205 16.584 ;
     RECT  8.869 1.152 9.209 5.208 ;
     RECT  8.381 6.72 9.209 6.744 ;
     RECT  9.205 7.728 9.241 16.584 ;
     RECT  9.209 3.552 9.299 5.208 ;
     RECT  9.233 0.096 9.316 0.12 ;
     RECT  9.316 0.096 9.317 0.168 ;
     RECT  9.299 3.648 9.317 5.208 ;
     RECT  9.317 3.84 9.443 5.208 ;
     RECT  9.241 7.728 9.445 16.68 ;
     RECT  9.445 7.728 9.497 16.968 ;
     RECT  9.317 0.144 9.533 0.168 ;
     RECT  9.497 12.96 9.541 16.968 ;
     RECT  9.313 17.952 9.541 17.976 ;
     RECT  9.443 4.704 9.817 5.208 ;
     RECT  9.541 12.96 9.997 17.976 ;
     RECT  9.817 4.704 10.001 5.4 ;
     RECT  9.209 1.152 10.073 2.376 ;
     RECT  9.497 7.728 10.217 11.784 ;
     RECT  10.172 0.528 10.451 0.552 ;
     RECT  10.073 1.728 10.645 2.376 ;
     RECT  10.217 9.024 10.645 11.784 ;
     RECT  9.997 12.96 10.645 18.024 ;
     RECT  10.501 0.096 10.721 0.12 ;
     RECT  10.645 9.024 10.825 18.024 ;
     RECT  10.825 9.024 10.865 18.072 ;
     RECT  10.865 10.848 10.897 18.072 ;
     RECT  10.001 4.704 11.077 5.208 ;
     RECT  10.897 10.848 11.149 18.12 ;
     RECT  10.597 19.248 11.149 19.272 ;
     RECT  10.645 1.728 11.173 2.904 ;
     RECT  11.149 10.848 11.185 19.272 ;
     RECT  11.077 4.56 11.293 5.208 ;
     RECT  11.173 1.728 11.297 2.952 ;
     RECT  10.217 7.728 11.405 7.752 ;
     RECT  11.293 4.56 11.411 5.592 ;
     RECT  11.297 1.728 11.699 2.904 ;
     RECT  11.411 4.56 11.749 5.112 ;
     RECT  11.185 10.848 11.869 19.416 ;
     RECT  10.865 9.024 12.017 9.336 ;
     RECT  12.037 0.096 12.133 0.12 ;
     RECT  12.133 0.096 12.305 0.216 ;
     RECT  11.749 3.984 12.332 5.112 ;
     RECT  12.305 0.192 12.341 0.216 ;
     RECT  11.869 10.704 12.589 19.416 ;
     RECT  12.332 3.744 12.625 5.112 ;
     RECT  11.699 1.728 12.697 2.376 ;
     RECT  12.625 3.744 12.697 5.4 ;
     RECT  12.697 1.728 12.733 5.4 ;
     RECT  12.733 1.728 12.949 5.832 ;
     RECT  12.949 1.728 13.093 6.12 ;
     RECT  12.017 9.024 13.093 9.096 ;
     RECT  13.093 1.728 13.208 7.368 ;
     RECT  13.093 8.448 13.208 9.096 ;
     RECT  12.589 10.08 13.208 19.416 ;
     RECT  13.189 0.24 13.381 0.264 ;
     RECT  13.381 0.24 13.429 0.36 ;
     RECT  13.429 0.144 13.477 0.36 ;
     RECT  13.208 1.728 13.565 19.416 ;
     RECT  13.477 0.144 13.765 0.552 ;
     RECT  13.565 8.304 14.033 19.416 ;
     RECT  13.765 0.096 14.291 0.552 ;
     RECT  13.565 1.728 14.293 6.552 ;
     RECT  14.033 10.848 14.321 19.416 ;
     RECT  14.033 8.304 14.357 9.816 ;
     RECT  14.357 8.4 14.537 9.816 ;
     RECT  14.293 1.728 14.917 5.736 ;
     RECT  14.537 8.496 15.347 9.816 ;
     RECT  14.917 1.152 15.401 5.736 ;
     RECT  15.401 1.152 15.545 4.776 ;
     RECT  15.347 9.12 15.649 9.816 ;
     RECT  14.321 11.424 15.649 19.416 ;
     RECT  15.649 9.12 16.085 19.416 ;
     RECT  16.085 9.12 16.129 19.32 ;
     RECT  16.129 9.12 16.337 18.936 ;
     RECT  15.545 1.152 16.517 4.248 ;
     RECT  16.517 1.728 16.769 4.248 ;
     RECT  16.769 3.12 16.801 4.248 ;
     RECT  16.337 9.504 16.883 18.936 ;
     RECT  14.291 0.096 17.221 0.12 ;
     RECT  16.883 9.504 17.237 17.64 ;
     RECT  17.237 13.104 17.353 17.64 ;
     RECT  16.801 3.12 17.377 5.16 ;
     RECT  17.449 6.864 17.605 6.888 ;
     RECT  17.377 3.12 17.633 5.208 ;
     RECT  17.605 6.768 17.633 6.888 ;
     RECT  17.633 6.768 17.701 6.792 ;
     RECT  16.769 1.728 17.797 1.8 ;
     RECT  17.633 3.12 17.797 5.112 ;
     RECT  17.353 13.296 17.939 17.64 ;
     RECT  17.221 0.096 17.989 0.216 ;
     RECT  17.797 1.728 17.989 5.112 ;
     RECT  16.883 18.768 17.989 18.936 ;
     RECT  17.989 18.768 18.101 19.32 ;
     RECT  17.237 9.504 18.133 12.024 ;
     RECT  18.133 9.072 18.373 12.024 ;
     RECT  18.373 8.352 18.469 12.024 ;
     RECT  17.939 13.296 18.469 17.448 ;
     RECT  18.101 18.768 18.469 19.272 ;
     RECT  18.469 8.352 18.529 17.448 ;
     RECT  17.989 0.096 18.608 5.112 ;
     RECT  17.701 6.096 18.608 6.792 ;
     RECT  18.529 8.208 18.608 17.448 ;
     RECT  18.608 0.096 18.904 17.448 ;
     RECT  18.904 6.096 18.961 17.448 ;
     RECT  18.469 18.672 19.091 19.272 ;
     RECT  19.091 18.672 19.187 18.84 ;
     RECT  18.961 6.096 19.249 17.688 ;
     RECT  19.249 6.096 19.613 18.216 ;
     RECT  19.613 6.288 20.189 18.216 ;
     RECT  20.189 13.392 20.339 18.216 ;
     RECT  20.339 13.392 20.627 18.168 ;
     RECT  18.904 0.096 20.797 5.112 ;
     RECT  20.797 0.048 20.945 5.112 ;
     RECT  20.627 13.392 21.107 17.256 ;
     RECT  21.107 13.392 21.625 17.208 ;
     RECT  21.589 18.768 21.683 18.792 ;
     RECT  20.189 6.288 22.172 12.216 ;
     RECT  21.625 13.296 22.172 17.208 ;
     RECT  22.172 6.288 22.259 17.208 ;
     RECT  20.945 0.048 22.601 4.68 ;
     RECT  22.259 6.288 22.889 12.216 ;
     RECT  22.601 0.048 22.925 4.44 ;
     RECT  22.259 13.296 22.981 17.208 ;
     RECT  22.925 0.048 22.997 4.344 ;
     RECT  22.789 19.104 23.173 19.128 ;
     RECT  22.889 6.576 23.533 12.216 ;
     RECT  22.981 13.296 23.533 17.256 ;
     RECT  23.533 6.576 23.941 17.256 ;
     RECT  22.997 0.048 24.008 4.248 ;
     RECT  23.941 6.576 24.008 17.448 ;
     RECT  23.173 19.104 24.037 19.224 ;
     RECT  24.037 19.008 24.133 19.224 ;
     RECT  24.008 0.048 24.277 17.448 ;
     RECT  24.133 18.912 24.277 19.224 ;
     RECT  24.277 0.048 24.304 17.496 ;
     RECT  24.277 18.912 24.373 19.272 ;
     RECT  24.373 18.576 24.509 19.272 ;
     RECT  24.509 18.672 24.515 19.272 ;
     RECT  24.515 18.768 24.553 19.272 ;
     RECT  24.304 6.912 24.761 7.464 ;
     RECT  24.304 8.736 24.865 17.496 ;
     RECT  24.553 19.248 25.043 19.272 ;
     RECT  24.865 8.736 25.715 17.688 ;
     RECT  25.715 8.736 25.765 17.64 ;
     RECT  25.765 8.496 25.769 17.64 ;
     RECT  24.304 0.048 25.877 4.248 ;
     RECT  24.761 7.392 26.233 7.464 ;
     RECT  25.769 8.496 26.273 12.84 ;
     RECT  26.233 7.344 26.317 7.464 ;
     RECT  26.273 8.496 26.332 11.544 ;
     RECT  26.332 9.696 26.381 11.544 ;
     RECT  26.381 9.696 26.525 11.4 ;
     RECT  26.317 7.392 26.701 7.464 ;
     RECT  26.701 7.392 26.741 8.088 ;
     RECT  25.769 13.824 26.953 17.64 ;
     RECT  26.953 13.824 27.133 17.688 ;
     RECT  26.525 10.272 27.281 11.4 ;
     RECT  25.877 0.048 27.317 3.048 ;
     RECT  27.317 2.736 27.497 3.048 ;
     RECT  27.281 10.704 27.605 11.4 ;
     RECT  27.317 0.048 27.641 1.56 ;
     RECT  26.273 12.528 27.713 12.84 ;
     RECT  27.953 19.296 28.037 19.32 ;
     RECT  26.741 8.064 28.145 8.088 ;
     RECT  27.133 13.824 28.213 18.264 ;
     RECT  27.641 0.048 28.217 1.512 ;
     RECT  28.217 0.048 28.253 1.464 ;
     RECT  27.713 12.528 28.393 12.552 ;
     RECT  25.877 4.224 28.433 4.248 ;
     RECT  28.213 13.824 28.499 18.888 ;
     RECT  28.499 13.824 28.787 17.784 ;
     RECT  28.253 0.816 29.045 1.464 ;
     RECT  28.499 18.816 29.113 18.888 ;
     RECT  29.045 1.392 29.408 1.464 ;
     RECT  27.497 3.024 29.408 3.048 ;
     RECT  27.605 10.704 29.408 11.256 ;
     RECT  28.393 12.24 29.408 12.552 ;
     RECT  28.787 13.824 29.408 17.688 ;
     RECT  29.408 1.392 29.512 17.688 ;
     RECT  29.512 2.418 29.704 17.688 ;
     RECT  29.113 18.816 29.845 18.936 ;
     RECT  29.704 17.088 29.98 17.688 ;
     RECT  29.704 10.704 30.017 10.728 ;
     RECT  29.845 18.816 30.035 19.272 ;
     RECT  29.98 17.472 30.085 17.688 ;
     RECT  29.704 14.496 30.089 16.104 ;
     RECT  30.035 19.248 30.131 19.272 ;
     RECT  29.704 12.24 30.233 12.696 ;
     RECT  30.085 17.472 30.323 17.736 ;
     RECT  29.512 1.392 30.413 1.416 ;
     RECT  30.089 15.024 30.419 16.104 ;
     RECT  30.323 17.616 30.457 17.736 ;
     RECT  30.419 15.024 30.46 15.048 ;
     RECT  30.457 17.664 30.515 17.736 ;
     RECT  30.233 12.672 30.593 12.696 ;
     RECT  30.515 17.712 30.611 17.736 ;
     RECT  30.653 19.296 30.737 19.32 ;
     RECT  29.704 3.024 33.037 3.048 ;
     RECT  33.037 3.024 34.524 3.144 ;
    LAYER M5 ;
     RECT  0.72 0.016 21.96 0.227 ;
     RECT  20.112 0.227 21.96 0.995 ;
     RECT  20.208 0.995 21.96 1.859 ;
     RECT  24 2.137 24.12 2.151 ;
     RECT  29.4 2.137 29.52 2.151 ;
     RECT  0.72 0.227 19.08 2.339 ;
     RECT  9.84 2.339 9.864 2.387 ;
     RECT  11.088 2.339 19.08 2.387 ;
     RECT  11.088 2.387 18.912 2.435 ;
     RECT  20.208 1.859 21.384 2.531 ;
     RECT  20.208 2.531 21.288 2.677 ;
     RECT  0.72 2.339 8.712 2.915 ;
     RECT  20.064 2.677 21.288 2.915 ;
     RECT  20.064 2.915 21 3.347 ;
     RECT  11.088 2.435 11.784 3.733 ;
     RECT  12.912 2.435 18.912 3.733 ;
     RECT  9.264 3.541 9.288 3.827 ;
     RECT  11.088 3.733 18.912 3.829 ;
     RECT  20.064 3.347 20.088 3.829 ;
     RECT  0.72 2.915 8.232 4.019 ;
     RECT  11.088 3.829 20.088 4.019 ;
     RECT  0.72 4.019 8.112 4.595 ;
     RECT  11.088 4.019 16.296 5.077 ;
     RECT  10.752 5.077 16.296 5.219 ;
     RECT  11.376 5.219 16.296 5.603 ;
     RECT  11.664 5.603 16.296 5.747 ;
     RECT  6.624 4.595 8.112 5.795 ;
     RECT  11.664 5.747 15.048 6.563 ;
     RECT  24 2.151 24.312 6.805 ;
     RECT  23.376 6.805 24.312 7.235 ;
     RECT  0.72 4.595 5.208 7.379 ;
     RECT  11.664 6.563 13.656 7.717 ;
     RECT  7.8 5.795 8.112 7.765 ;
     RECT  9.408 3.829 9.432 7.765 ;
     RECT  22.32 7.189 22.344 7.765 ;
     RECT  15.024 6.563 15.048 8.485 ;
     RECT  16.272 5.747 16.296 8.485 ;
     RECT  1.296 7.379 5.208 8.627 ;
     RECT  1.296 8.627 2.856 8.771 ;
     RECT  21.36 7.765 22.344 9.013 ;
     RECT  10.944 7.717 13.656 9.059 ;
     RECT  11.664 9.059 13.656 9.107 ;
     RECT  7.8 7.765 9.432 9.109 ;
     RECT  15.024 8.485 16.296 9.539 ;
     RECT  21.36 9.013 22.824 9.731 ;
     RECT  26.256 7.333 26.28 9.731 ;
     RECT  1.296 8.771 2.808 9.827 ;
     RECT  7.8 9.109 10.392 10.019 ;
     RECT  21.36 9.731 22.344 10.307 ;
     RECT  1.296 9.827 1.32 10.355 ;
     RECT  11.664 9.107 11.688 10.837 ;
     RECT  2.4 9.827 2.808 10.883 ;
     RECT  12.672 9.107 13.656 10.931 ;
     RECT  11.376 10.837 11.688 10.933 ;
     RECT  11.376 10.933 11.784 11.317 ;
     RECT  16.272 9.539 16.296 11.459 ;
     RECT  26.208 10.117 26.232 11.555 ;
     RECT  21.36 10.307 21.912 11.845 ;
     RECT  6.624 5.795 6.648 11.987 ;
     RECT  15.024 9.539 15.048 12.035 ;
     RECT  2.4 10.883 2.712 12.517 ;
     RECT  3.888 8.627 5.208 12.517 ;
     RECT  24 7.235 24.312 12.517 ;
     RECT  17.28 4.019 20.088 12.563 ;
     RECT  13.008 10.931 13.656 12.757 ;
     RECT  10.8 11.317 11.784 12.997 ;
     RECT  7.8 10.019 9.432 13.091 ;
     RECT  13.008 12.757 14.232 13.093 ;
     RECT  21.36 11.845 21.96 13.093 ;
     RECT  24 12.517 24.6 13.333 ;
     RECT  25.68 12.469 25.704 13.333 ;
     RECT  10.8 12.997 11.928 13.525 ;
     RECT  12.912 13.093 14.232 13.525 ;
     RECT  17.28 12.563 19.896 13.621 ;
     RECT  2.4 12.517 5.208 13.667 ;
     RECT  24 13.333 25.704 13.669 ;
     RECT  10.8 13.525 14.232 13.763 ;
     RECT  15.36 12.517 15.96 13.859 ;
     RECT  10.8 13.763 13.656 13.861 ;
     RECT  21.36 13.093 22.248 14.197 ;
     RECT  23.328 13.669 25.704 14.197 ;
     RECT  26.688 14.149 26.712 14.197 ;
     RECT  7.8 13.091 8.856 14.245 ;
     RECT  9.936 13.861 13.656 14.245 ;
     RECT  26.688 14.197 26.904 14.389 ;
     RECT  28.368 14.197 28.392 14.389 ;
     RECT  17.088 13.621 20.232 14.435 ;
     RECT  15.936 13.859 15.96 14.581 ;
     RECT  21.36 14.197 25.704 14.725 ;
     RECT  26.688 14.389 28.392 14.725 ;
     RECT  7.8 14.245 13.656 14.773 ;
     RECT  29.4 2.151 29.712 14.773 ;
     RECT  17.616 14.435 19.896 14.963 ;
     RECT  29.4 14.773 29.88 15.013 ;
     RECT  3.888 13.667 5.208 15.443 ;
     RECT  21.36 14.725 28.392 15.443 ;
     RECT  7.8 14.773 14.184 15.733 ;
     RECT  15.936 14.581 16.248 15.733 ;
     RECT  17.616 14.963 18.912 15.925 ;
     RECT  4.032 15.443 5.208 16.019 ;
     RECT  21.696 15.443 28.392 16.019 ;
     RECT  29.4 15.013 30.408 16.115 ;
     RECT  7.8 15.733 16.248 16.163 ;
     RECT  4.32 16.019 5.208 16.307 ;
     RECT  9.456 16.163 16.248 16.309 ;
     RECT  17.616 15.925 19.56 16.549 ;
     RECT  9.456 16.309 16.488 16.643 ;
     RECT  15.504 16.643 16.488 16.693 ;
     RECT  4.32 16.307 4.344 16.835 ;
     RECT  15.504 16.693 16.584 16.981 ;
     RECT  17.616 16.549 20.232 16.981 ;
     RECT  15.504 16.981 20.232 17.077 ;
     RECT  21.696 16.019 28.296 17.077 ;
     RECT  29.4 16.115 29.88 17.077 ;
     RECT  2.4 13.667 2.712 17.289 ;
     RECT  7.8 16.163 8.112 17.289 ;
     RECT  2.4 17.289 2.52 17.303 ;
     RECT  7.8 17.289 7.92 17.303 ;
     RECT  15.504 17.077 29.928 17.461 ;
     RECT  9.456 16.643 14.472 17.605 ;
     RECT  15.504 17.461 30.312 17.605 ;
     RECT  9.456 17.605 30.408 17.653 ;
     RECT  9.456 17.653 30.504 17.701 ;
     RECT  9.456 17.701 30.6 19.285 ;
     RECT  9.456 19.285 30.696 19.408 ;
     RECT  19.08 0.227 20.112 0.995 ;
     RECT  19.08 0.995 20.208 2.387 ;
     RECT  8.712 2.339 9.84 2.387 ;
     RECT  9.864 2.339 11.088 2.387 ;
     RECT  8.712 2.387 9.432 2.915 ;
     RECT  18.912 2.387 20.208 2.677 ;
     RECT  11.784 2.435 12.912 3.733 ;
     RECT  18.912 2.677 20.064 3.829 ;
     RECT  8.232 2.915 9.432 3.541 ;
     RECT  8.232 3.541 9.264 3.827 ;
     RECT  9.288 3.541 9.432 3.827 ;
     RECT  8.232 3.827 9.432 3.829 ;
     RECT  8.232 3.829 9.408 4.019 ;
     RECT  8.112 4.019 9.408 7.765 ;
     RECT  16.296 4.019 17.28 11.459 ;
     RECT  5.208 4.595 6.624 11.987 ;
     RECT  9.432 5.077 10.752 5.219 ;
     RECT  15.048 5.747 16.272 8.485 ;
     RECT  6.648 5.795 7.8 11.987 ;
     RECT  13.656 6.563 15.024 12.035 ;
     RECT  22.344 7.189 23.376 7.235 ;
     RECT  9.432 7.717 10.944 9.059 ;
     RECT  20.088 7.765 21.36 12.563 ;
     RECT  2.856 8.627 3.888 8.771 ;
     RECT  2.808 8.771 3.888 10.883 ;
     RECT  22.824 9.013 24 9.731 ;
     RECT  9.432 9.059 11.664 9.109 ;
     RECT  11.688 9.107 12.672 10.931 ;
     RECT  10.392 9.109 11.664 10.019 ;
     RECT  15.048 9.539 16.272 11.459 ;
     RECT  1.32 9.827 2.4 10.355 ;
     RECT  9.432 10.019 11.664 10.837 ;
     RECT  9.432 10.837 11.376 11.317 ;
     RECT  2.712 10.883 3.888 12.517 ;
     RECT  11.688 10.931 13.008 10.933 ;
     RECT  11.784 10.933 13.008 12.997 ;
     RECT  9.432 11.317 10.8 13.091 ;
     RECT  15.048 11.459 17.28 12.035 ;
     RECT  13.656 12.035 17.28 12.517 ;
     RECT  24.312 12.469 25.68 12.517 ;
     RECT  13.656 12.517 15.36 12.757 ;
     RECT  15.96 12.517 17.28 13.621 ;
     RECT  24.6 12.517 25.68 13.333 ;
     RECT  19.896 12.563 21.36 13.621 ;
     RECT  14.232 12.757 15.36 13.763 ;
     RECT  11.928 12.997 13.008 13.093 ;
     RECT  8.856 13.091 10.8 13.861 ;
     RECT  11.928 13.093 12.912 13.525 ;
     RECT  15.96 13.621 17.088 14.435 ;
     RECT  20.232 13.621 21.36 14.435 ;
     RECT  2.712 13.667 3.888 15.443 ;
     RECT  22.248 13.669 23.328 14.197 ;
     RECT  13.656 13.763 15.36 13.859 ;
     RECT  13.656 13.859 14.184 14.773 ;
     RECT  8.856 13.861 9.936 14.245 ;
     RECT  25.704 14.149 26.688 14.725 ;
     RECT  26.904 14.197 28.368 14.389 ;
     RECT  28.392 14.197 29.4 16.019 ;
     RECT  15.96 14.435 17.616 14.581 ;
     RECT  19.896 14.435 21.36 14.963 ;
     RECT  16.248 14.581 17.616 16.309 ;
     RECT  18.912 14.963 19.56 15.925 ;
     RECT  2.712 15.443 4.032 16.019 ;
     RECT  21.36 15.443 21.696 16.549 ;
     RECT  28.296 16.019 29.4 17.077 ;
     RECT  29.88 16.115 30.408 17.077 ;
     RECT  8.112 16.163 9.456 17.289 ;
     RECT  16.488 16.309 17.616 16.693 ;
     RECT  20.232 16.549 21.696 17.077 ;
     RECT  14.472 16.643 15.504 17.605 ;
     RECT  16.584 16.693 17.616 16.981 ;
     RECT  29.928 17.077 30.408 17.461 ;
     RECT  30.312 17.461 30.408 17.605 ;
  END
END dsfd_rly_214_NS
END LIBRARY
